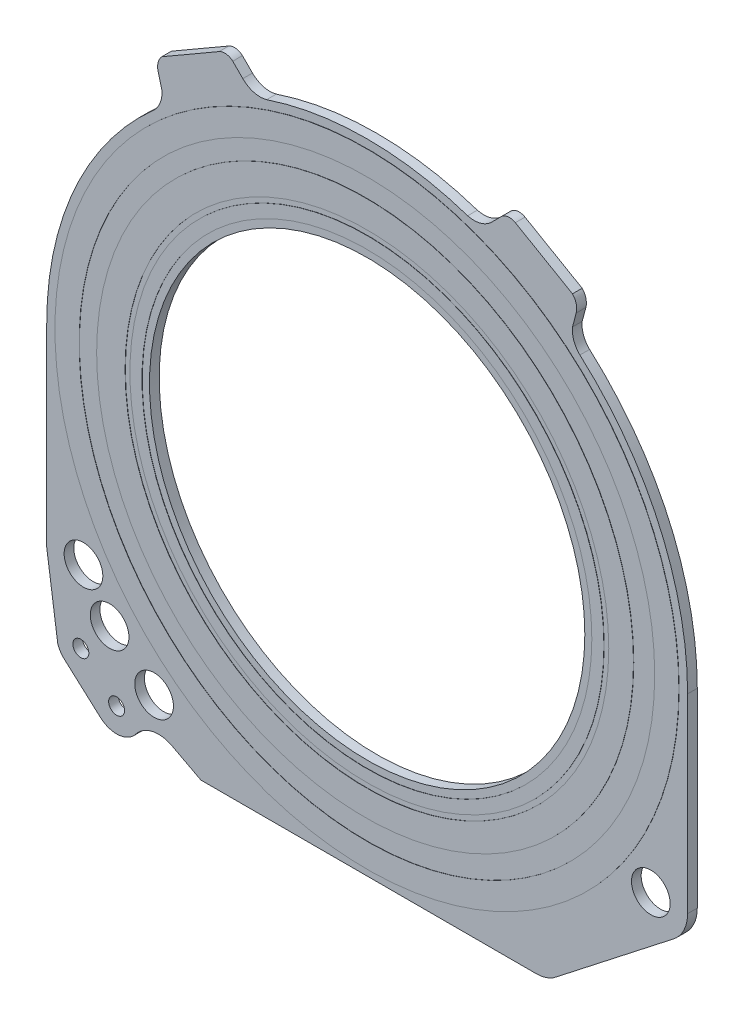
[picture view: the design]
ISO-10303-21;
HEADER;
FILE_DESCRIPTION(('STEP AP214'),'2;1');
FILE_NAME('part.step','',(''),(''),'','','');
FILE_SCHEMA(('AUTOMOTIVE_DESIGN { 1 0 10303 214 1 1 1 1 }'));
ENDSEC;
DATA;
#1=APPLICATION_CONTEXT('core data for automotive mechanical design processes');
#2=APPLICATION_PROTOCOL_DEFINITION('international standard','automotive_design',2000,#1);
#3=PRODUCT_CONTEXT('',#1,'mechanical');
#4=PRODUCT('Part','Part','',(#3));
#5=PRODUCT_RELATED_PRODUCT_CATEGORY('part','',(#4));
#6=PRODUCT_DEFINITION_FORMATION('','',#4);
#7=PRODUCT_DEFINITION_CONTEXT('part definition',#1,'design');
#8=PRODUCT_DEFINITION('design','',#6,#7);
#9=PRODUCT_DEFINITION_SHAPE('','',#8);
#10=(LENGTH_UNIT() NAMED_UNIT(*) SI_UNIT(.MILLI.,.METRE.));
#11=(NAMED_UNIT(*) PLANE_ANGLE_UNIT() SI_UNIT($,.RADIAN.));
#12=(NAMED_UNIT(*) SI_UNIT($,.STERADIAN.) SOLID_ANGLE_UNIT());
#13=UNCERTAINTY_MEASURE_WITH_UNIT(LENGTH_MEASURE(1.E-05),#10,'distance_accuracy_value','');
#14=(GEOMETRIC_REPRESENTATION_CONTEXT(3) GLOBAL_UNCERTAINTY_ASSIGNED_CONTEXT((#13)) GLOBAL_UNIT_ASSIGNED_CONTEXT((#10,
#11,#12)) REPRESENTATION_CONTEXT('',''));
#15=CARTESIAN_POINT('',(0.,0.,0.));
#16=DIRECTION('',(0.,0.,1.));
#17=DIRECTION('',(1.,0.,0.));
#18=AXIS2_PLACEMENT_3D('',#15,#16,#17);
#19=CARTESIAN_POINT('',(72.2071972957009,20.3682152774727,0.));
#20=DIRECTION('',(0.,0.,1.));
#21=DIRECTION('',(1.,0.,0.));
#22=AXIS2_PLACEMENT_3D('',#19,#20,#21);
#23=PLANE('',#22);
#24=CARTESIAN_POINT('',(72.2834094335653,20.3510273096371,0.));
#25=DIRECTION('',(0.,0.,1.));
#26=DIRECTION('',(1.,0.,0.));
#27=AXIS2_PLACEMENT_3D('',#24,#25,#26);
#28=CIRCLE('',#27,10.);
#29=CARTESIAN_POINT('',(82.2834094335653,20.3510273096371,0.));
#30=VERTEX_POINT('',#29);
#31=EDGE_CURVE('E25',#30,#30,#28,.F.);
#32=ORIENTED_EDGE('',*,*,#31,.F.);
#33=EDGE_LOOP('',(#32));
#34=FACE_BOUND('',#33,.T.);
#35=CARTESIAN_POINT('',(72.2834094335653,20.3510273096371,0.));
#36=DIRECTION('',(0.,0.,1.));
#37=DIRECTION('',(1.,0.,0.));
#38=AXIS2_PLACEMENT_3D('',#35,#36,#37);
#39=CIRCLE('',#38,9.79999999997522);
#40=CARTESIAN_POINT('',(82.0834094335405,20.3510273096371,0.));
#41=VERTEX_POINT('',#40);
#42=EDGE_CURVE('E462',#41,#41,#39,.T.);
#43=ORIENTED_EDGE('',*,*,#42,.F.);
#44=EDGE_LOOP('',(#43));
#45=FACE_BOUND('',#44,.T.);
#46=ADVANCED_FACE('F17',(#34,#45),#23,.T.);
#47=CARTESIAN_POINT('',(72.2834094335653,20.3510273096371,0.));
#48=DIRECTION('',(0.,0.,1.));
#49=DIRECTION('',(1.,0.,0.));
#50=AXIS2_PLACEMENT_3D('',#47,#48,#49);
#51=CIRCLE('',#50,11.9);
#52=CARTESIAN_POINT('',(84.1834094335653,20.3510273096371,0.));
#53=VERTEX_POINT('',#52);
#54=EDGE_CURVE('E396',#53,#53,#51,.F.);
#55=ORIENTED_EDGE('',*,*,#54,.F.);
#56=EDGE_LOOP('',(#55));
#57=FACE_BOUND('',#56,.T.);
#58=CARTESIAN_POINT('',(72.2071972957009,20.3682152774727,0.));
#59=DIRECTION('',(0.,0.,1.));
#60=DIRECTION('',(1.,0.,0.));
#61=AXIS2_PLACEMENT_3D('',#58,#59,#60);
#62=CIRCLE('',#61,11.1);
#63=CARTESIAN_POINT('',(83.3071972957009,20.3682152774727,0.));
#64=VERTEX_POINT('',#63);
#65=EDGE_CURVE('E472',#64,#64,#62,.T.);
#66=ORIENTED_EDGE('',*,*,#65,.F.);
#67=EDGE_LOOP('',(#66));
#68=FACE_BOUND('',#67,.T.);
#69=ADVANCED_FACE('F457',(#57,#68),#23,.T.);
#70=CARTESIAN_POINT('',(72.2071972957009,20.3682152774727,0.));
#71=DIRECTION('',(0.,0.,1.));
#72=DIRECTION('',(1.,0.,0.));
#73=AXIS2_PLACEMENT_3D('',#70,#71,#72);
#74=CIRCLE('',#73,13.173799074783);
#75=CARTESIAN_POINT('',(63.4602832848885,30.2191277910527,0.));
#76=VERTEX_POINT('',#75);
#77=CARTESIAN_POINT('',(59.0334094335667,20.3510273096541,0.));
#78=VERTEX_POINT('',#77);
#79=EDGE_CURVE('E210',#76,#78,#74,.T.);
#80=ORIENTED_EDGE('',*,*,#79,.T.);
#81=DIRECTION('',(0.,-1.,0.));
#82=VECTOR('',#81,1.);
#83=CARTESIAN_POINT('',(59.0334094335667,20.3510273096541,0.));
#84=LINE('',#83,#82);
#85=CARTESIAN_POINT('',(59.0334094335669,12.3510273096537,0.));
#86=VERTEX_POINT('',#85);
#87=EDGE_CURVE('E220',#78,#86,#84,.T.);
#88=ORIENTED_EDGE('',*,*,#87,.T.);
#89=DIRECTION('',(0.140192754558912,-0.990124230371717,0.));
#90=VECTOR('',#89,1.);
#91=CARTESIAN_POINT('',(59.0334094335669,12.3510273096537,0.));
#92=LINE('',#91,#90);
#93=CARTESIAN_POINT('',(59.4881770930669,9.1391888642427,0.));
#94=VERTEX_POINT('',#93);
#95=EDGE_CURVE('E225',#86,#94,#92,.T.);
#96=ORIENTED_EDGE('',*,*,#95,.T.);
#97=CARTESIAN_POINT('',(60.3937369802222,9.40788438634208,0.));
#98=DIRECTION('',(0.,0.,1.));
#99=DIRECTION('',(1.,0.,0.));
#100=AXIS2_PLACEMENT_3D('',#97,#98,#99);
#101=CIRCLE('',#100,0.944582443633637);
#102=CARTESIAN_POINT('',(59.79093414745,8.6806535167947,0.));
#103=VERTEX_POINT('',#102);
#104=EDGE_CURVE('E239',#94,#103,#101,.T.);
#105=ORIENTED_EDGE('',*,*,#104,.T.);
#106=DIRECTION('',(0.744428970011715,-0.667701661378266,0.));
#107=VECTOR('',#106,1.);
#108=CARTESIAN_POINT('',(59.79093414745,8.6806535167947,0.));
#109=LINE('',#108,#107);
#110=CARTESIAN_POINT('',(61.2703050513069,7.3537594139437,0.));
#111=VERTEX_POINT('',#110);
#112=EDGE_CURVE('E242',#103,#111,#109,.T.);
#113=ORIENTED_EDGE('',*,*,#112,.T.);
#114=CARTESIAN_POINT('',(61.9234094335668,8.11102730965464,0.));
#115=DIRECTION('',(0.,0.,1.));
#116=DIRECTION('',(1.,0.,0.));
#117=AXIS2_PLACEMENT_3D('',#114,#115,#116);
#118=CIRCLE('',#117,1.00000000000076);
#119=CARTESIAN_POINT('',(62.713227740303,7.4976864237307,0.));
#120=VERTEX_POINT('',#119);
#121=EDGE_CURVE('E245',#111,#120,#118,.T.);
#122=ORIENTED_EDGE('',*,*,#121,.T.);
#123=CARTESIAN_POINT('',(63.6597167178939,6.7821213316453,0.));
#124=DIRECTION('',(0.,0.,-1.));
#125=DIRECTION('',(1.,0.,0.));
#126=AXIS2_PLACEMENT_3D('',#123,#124,#125);
#127=CIRCLE('',#126,1.18653899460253);
#128=CARTESIAN_POINT('',(64.1660247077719,7.8552135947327,0.));
#129=VERTEX_POINT('',#128);
#130=EDGE_CURVE('E248',#120,#129,#127,.T.);
#131=ORIENTED_EDGE('',*,*,#130,.T.);
#132=DIRECTION('',(0.884984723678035,-0.465620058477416,0.));
#133=VECTOR('',#132,1.);
#134=CARTESIAN_POINT('',(64.1660247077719,7.8552135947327,0.));
#135=LINE('',#134,#133);
#136=CARTESIAN_POINT('',(65.4094094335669,7.2010273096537,0.));
#137=VERTEX_POINT('',#136);
#138=EDGE_CURVE('E251',#129,#137,#135,.T.);
#139=ORIENTED_EDGE('',*,*,#138,.T.);
#140=DIRECTION('',(1.,0.,0.));
#141=VECTOR('',#140,1.);
#142=CARTESIAN_POINT('',(65.4094094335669,7.2010273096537,0.));
#143=LINE('',#142,#141);
#144=CARTESIAN_POINT('',(79.2751515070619,7.2010273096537,0.));
#145=VERTEX_POINT('',#144);
#146=EDGE_CURVE('E254',#137,#145,#143,.T.);
#147=ORIENTED_EDGE('',*,*,#146,.T.);
#148=CARTESIAN_POINT('',(79.2751515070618,8.50102730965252,0.));
#149=DIRECTION('',(0.,0.,1.));
#150=DIRECTION('',(1.,0.,0.));
#151=AXIS2_PLACEMENT_3D('',#148,#149,#150);
#152=CIRCLE('',#151,1.29999999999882);
#153=CARTESIAN_POINT('',(80.1002135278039,7.4964016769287,0.));
#154=VERTEX_POINT('',#153);
#155=EDGE_CURVE('E257',#145,#154,#152,.T.);
#156=ORIENTED_EDGE('',*,*,#155,.T.);
#157=DIRECTION('',(0.78818503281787,0.615438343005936,0.));
#158=VECTOR('',#157,1.);
#159=CARTESIAN_POINT('',(80.1002135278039,7.4964016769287,0.));
#160=LINE('',#159,#158);
#161=CARTESIAN_POINT('',(84.9489566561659,11.2824446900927,0.));
#162=VERTEX_POINT('',#161);
#163=EDGE_CURVE('E260',#154,#162,#160,.T.);
#164=ORIENTED_EDGE('',*,*,#163,.T.);
#165=CARTESIAN_POINT('',(84.0134094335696,12.4804227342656,0.));
#166=DIRECTION('',(0.,0.,1.));
#167=DIRECTION('',(1.,0.,0.));
#168=AXIS2_PLACEMENT_3D('',#165,#166,#167);
#169=CIRCLE('',#168,1.52000000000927);
#170=CARTESIAN_POINT('',(85.5334094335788,12.4804227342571,0.));
#171=VERTEX_POINT('',#170);
#172=EDGE_CURVE('E263',#162,#171,#169,.T.);
#173=ORIENTED_EDGE('',*,*,#172,.T.);
#174=DIRECTION('',(0.,1.,0.));
#175=VECTOR('',#174,1.);
#176=CARTESIAN_POINT('',(85.5334094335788,12.4804227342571,0.));
#177=LINE('',#176,#175);
#178=CARTESIAN_POINT('',(85.5334094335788,20.3510273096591,0.));
#179=VERTEX_POINT('',#178);
#180=EDGE_CURVE('E266',#171,#179,#177,.T.);
#181=ORIENTED_EDGE('',*,*,#180,.T.);
#182=CARTESIAN_POINT('',(72.2834094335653,20.3510273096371,0.));
#183=DIRECTION('',(0.,0.,1.));
#184=DIRECTION('',(1.,0.,0.));
#185=AXIS2_PLACEMENT_3D('',#182,#183,#184);
#186=CIRCLE('',#185,13.2500000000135);
#187=CARTESIAN_POINT('',(81.0802834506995,30.2594836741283,0.));
#188=VERTEX_POINT('',#187);
#189=EDGE_CURVE('E269',#179,#188,#186,.T.);
#190=ORIENTED_EDGE('',*,*,#189,.T.);
#191=CARTESIAN_POINT('',(81.790227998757,30.9954268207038,0.));
#192=DIRECTION('',(0.,0.,-1.));
#193=DIRECTION('',(1.,0.,0.));
#194=AXIS2_PLACEMENT_3D('',#191,#192,#193);
#195=CIRCLE('',#194,1.02256226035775);
#196=CARTESIAN_POINT('',(80.7740510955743,31.1095236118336,0.));
#197=VERTEX_POINT('',#196);
#198=EDGE_CURVE('E272',#188,#197,#195,.T.);
#199=ORIENTED_EDGE('',*,*,#198,.T.);
#200=DIRECTION('',(0.255800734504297,0.966729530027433,0.));
#201=VECTOR('',#200,1.);
#202=CARTESIAN_POINT('',(80.7740510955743,31.1095236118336,0.));
#203=LINE('',#202,#201);
#204=CARTESIAN_POINT('',(80.9265181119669,31.6857313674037,0.));
#205=VERTEX_POINT('',#204);
#206=EDGE_CURVE('E275',#197,#205,#203,.T.);
#207=ORIENTED_EDGE('',*,*,#206,.T.);
#208=CARTESIAN_POINT('',(80.2953420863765,31.8527432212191,0.));
#209=DIRECTION('',(0.,0.,1.));
#210=DIRECTION('',(1.,0.,0.));
#211=AXIS2_PLACEMENT_3D('',#208,#209,#210);
#212=CIRCLE('',#211,0.652898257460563);
#213=CARTESIAN_POINT('',(80.7740510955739,32.2967182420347,0.));
#214=VERTEX_POINT('',#213);
#215=EDGE_CURVE('E278',#205,#214,#212,.T.);
#216=ORIENTED_EDGE('',*,*,#215,.T.);
#217=DIRECTION('',(-0.865868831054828,0.500271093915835,0.));
#218=VECTOR('',#217,1.);
#219=CARTESIAN_POINT('',(80.7740510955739,32.2967182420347,0.));
#220=LINE('',#219,#218);
#221=CARTESIAN_POINT('',(78.411036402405,33.6619919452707,0.));
#222=VERTEX_POINT('',#221);
#223=EDGE_CURVE('E281',#214,#222,#220,.T.);
#224=ORIENTED_EDGE('',*,*,#223,.T.);
#225=CARTESIAN_POINT('',(78.1669553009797,33.2395365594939,0.));
#226=DIRECTION('',(0.,0.,1.));
#227=DIRECTION('',(1.,0.,0.));
#228=AXIS2_PLACEMENT_3D('',#225,#226,#227);
#229=CIRCLE('',#228,0.487897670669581);
#230=CARTESIAN_POINT('',(77.8410630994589,33.6026321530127,0.));
#231=VERTEX_POINT('',#230);
#232=EDGE_CURVE('E284',#222,#231,#229,.T.);
#233=ORIENTED_EDGE('',*,*,#232,.T.);
#234=DIRECTION('',(-0.707181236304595,-0.70703231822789,0.));
#235=VECTOR('',#234,1.);
#236=CARTESIAN_POINT('',(77.4254574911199,33.1871140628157,0.));
#237=LINE('',#236,#235);
#238=CARTESIAN_POINT('',(77.4254574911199,33.1871140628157,0.));
#239=VERTEX_POINT('',#238);
#240=EDGE_CURVE('E287',#231,#239,#237,.T.);
#241=ORIENTED_EDGE('',*,*,#240,.T.);
#242=CARTESIAN_POINT('',(76.7078520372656,33.9048706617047,0.));
#243=DIRECTION('',(0.,0.,-1.));
#244=DIRECTION('',(1.,0.,0.));
#245=AXIS2_PLACEMENT_3D('',#242,#243,#244);
#246=CIRCLE('',#245,1.01495424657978);
#247=CARTESIAN_POINT('',(76.4398783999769,32.9259313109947,0.));
#248=VERTEX_POINT('',#247);
#249=EDGE_CURVE('E290',#239,#248,#246,.T.);
#250=ORIENTED_EDGE('',*,*,#249,.T.);
#251=CARTESIAN_POINT('',(72.283409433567,20.4673099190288,0.));
#252=DIRECTION('',(0.,0.,1.));
#253=DIRECTION('',(1.,0.,0.));
#254=AXIS2_PLACEMENT_3D('',#251,#252,#253);
#255=CIRCLE('',#254,13.1336773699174);
#256=CARTESIAN_POINT('',(68.1269404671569,32.9259313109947,0.));
#257=VERTEX_POINT('',#256);
#258=EDGE_CURVE('E293',#248,#257,#255,.T.);
#259=ORIENTED_EDGE('',*,*,#258,.T.);
#260=CARTESIAN_POINT('',(67.8589668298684,33.9048706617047,0.));
#261=DIRECTION('',(0.,0.,-1.));
#262=DIRECTION('',(1.,0.,0.));
#263=AXIS2_PLACEMENT_3D('',#260,#261,#262);
#264=CIRCLE('',#263,1.01495424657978);
#265=CARTESIAN_POINT('',(67.1413613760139,33.1871140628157,0.));
#266=VERTEX_POINT('',#265);
#267=EDGE_CURVE('E296',#257,#266,#264,.T.);
#268=ORIENTED_EDGE('',*,*,#267,.T.);
#269=DIRECTION('',(-0.707181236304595,0.70703231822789,0.));
#270=VECTOR('',#269,1.);
#271=CARTESIAN_POINT('',(67.1413613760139,33.1871140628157,0.));
#272=LINE('',#271,#270);
#273=CARTESIAN_POINT('',(66.7257557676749,33.6026321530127,0.));
#274=VERTEX_POINT('',#273);
#275=EDGE_CURVE('E299',#266,#274,#272,.T.);
#276=ORIENTED_EDGE('',*,*,#275,.T.);
#277=CARTESIAN_POINT('',(66.3998635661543,33.2395365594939,0.));
#278=DIRECTION('',(0.,0.,1.));
#279=DIRECTION('',(1.,0.,0.));
#280=AXIS2_PLACEMENT_3D('',#277,#278,#279);
#281=CIRCLE('',#280,0.487897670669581);
#282=CARTESIAN_POINT('',(66.155782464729,33.6619919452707,0.));
#283=VERTEX_POINT('',#282);
#284=EDGE_CURVE('E302',#274,#283,#281,.T.);
#285=ORIENTED_EDGE('',*,*,#284,.T.);
#286=DIRECTION('',(-0.865868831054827,-0.500271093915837,0.));
#287=VECTOR('',#286,1.);
#288=CARTESIAN_POINT('',(63.7927677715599,32.2967182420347,0.));
#289=LINE('',#288,#287);
#290=CARTESIAN_POINT('',(63.7927677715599,32.2967182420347,0.));
#291=VERTEX_POINT('',#290);
#292=EDGE_CURVE('E305',#283,#291,#289,.T.);
#293=ORIENTED_EDGE('',*,*,#292,.T.);
#294=CARTESIAN_POINT('',(64.2714767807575,31.8527432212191,0.));
#295=DIRECTION('',(0.,0.,1.));
#296=DIRECTION('',(1.,0.,0.));
#297=AXIS2_PLACEMENT_3D('',#294,#295,#296);
#298=CIRCLE('',#297,0.652898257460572);
#299=CARTESIAN_POINT('',(63.6403007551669,31.6857313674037,0.));
#300=VERTEX_POINT('',#299);
#301=EDGE_CURVE('E308',#291,#300,#298,.T.);
#302=ORIENTED_EDGE('',*,*,#301,.T.);
#303=DIRECTION('',(0.255800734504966,-0.966729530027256,0.));
#304=VECTOR('',#303,1.);
#305=CARTESIAN_POINT('',(63.6403007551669,31.6857313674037,0.));
#306=LINE('',#305,#304);
#307=CARTESIAN_POINT('',(63.7927677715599,31.1095236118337,0.));
#308=VERTEX_POINT('',#307);
#309=EDGE_CURVE('E311',#300,#308,#306,.T.);
#310=ORIENTED_EDGE('',*,*,#309,.T.);
#311=CARTESIAN_POINT('',(62.7210654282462,31.0024353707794,0.));
#312=DIRECTION('',(0.,0.,-1.));
#313=DIRECTION('',(1.,0.,0.));
#314=AXIS2_PLACEMENT_3D('',#311,#312,#313);
#315=CIRCLE('',#314,1.07703936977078);
#316=EDGE_CURVE('E230',#308,#76,#315,.T.);
#317=ORIENTED_EDGE('',*,*,#316,.T.);
#318=EDGE_LOOP('',(#80,#88,#96,#105,#113,#122,#131,#139,#147,#156,#164,#173,#181,#190,#199,#207,
#216,#224,#233,#241,#250,#259,#268,#276,#285,#293,#302,#310,#317));
#319=FACE_BOUND('',#318,.T.);
#320=CARTESIAN_POINT('',(84.0134094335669,12.4810273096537,0.));
#321=DIRECTION('',(0.,0.,1.));
#322=DIRECTION('',(1.,0.,0.));
#323=AXIS2_PLACEMENT_3D('',#320,#321,#322);
#324=CIRCLE('',#323,0.8);
#325=CARTESIAN_POINT('',(84.8134094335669,12.4810273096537,0.));
#326=VERTEX_POINT('',#325);
#327=EDGE_CURVE('E234',#326,#326,#324,.T.);
#328=ORIENTED_EDGE('',*,*,#327,.F.);
#329=EDGE_LOOP('',(#328));
#330=FACE_BOUND('',#329,.T.);
#331=CARTESIAN_POINT('',(63.4734094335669,9.2810273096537,0.));
#332=DIRECTION('',(0.,0.,1.));
#333=DIRECTION('',(1.,0.,0.));
#334=AXIS2_PLACEMENT_3D('',#331,#332,#333);
#335=CIRCLE('',#334,0.8);
#336=CARTESIAN_POINT('',(64.2734094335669,9.2810273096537,0.));
#337=VERTEX_POINT('',#336);
#338=EDGE_CURVE('E520',#337,#337,#335,.T.);
#339=ORIENTED_EDGE('',*,*,#338,.F.);
#340=EDGE_LOOP('',(#339));
#341=FACE_BOUND('',#340,.T.);
#342=CARTESIAN_POINT('',(61.6334094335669,10.8310273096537,0.));
#343=DIRECTION('',(0.,0.,1.));
#344=DIRECTION('',(1.,0.,0.));
#345=AXIS2_PLACEMENT_3D('',#342,#343,#344);
#346=CIRCLE('',#345,0.8);
#347=CARTESIAN_POINT('',(62.4334094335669,10.8310273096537,0.));
#348=VERTEX_POINT('',#347);
#349=EDGE_CURVE('E514',#348,#348,#346,.T.);
#350=ORIENTED_EDGE('',*,*,#349,.F.);
#351=EDGE_LOOP('',(#350));
#352=FACE_BOUND('',#351,.T.);
#353=CARTESIAN_POINT('',(60.553409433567,12.4810273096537,0.));
#354=DIRECTION('',(0.,0.,1.));
#355=DIRECTION('',(1.,0.,0.));
#356=AXIS2_PLACEMENT_3D('',#353,#354,#355);
#357=CIRCLE('',#356,0.8);
#358=CARTESIAN_POINT('',(61.353409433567,12.4810273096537,0.));
#359=VERTEX_POINT('',#358);
#360=EDGE_CURVE('E508',#359,#359,#357,.T.);
#361=ORIENTED_EDGE('',*,*,#360,.F.);
#362=EDGE_LOOP('',(#361));
#363=FACE_BOUND('',#362,.T.);
#364=CARTESIAN_POINT('',(60.4444881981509,9.4315398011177,0.));
#365=DIRECTION('',(0.,0.,1.));
#366=DIRECTION('',(1.,0.,0.));
#367=AXIS2_PLACEMENT_3D('',#364,#365,#366);
#368=CIRCLE('',#367,0.33);
#369=CARTESIAN_POINT('',(60.7744881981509,9.4315398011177,0.));
#370=VERTEX_POINT('',#369);
#371=EDGE_CURVE('E502',#370,#370,#368,.T.);
#372=ORIENTED_EDGE('',*,*,#371,.F.);
#373=EDGE_LOOP('',(#372));
#374=FACE_BOUND('',#373,.T.);
#375=CARTESIAN_POINT('',(61.9234094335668,8.11102730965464,0.));
#376=DIRECTION('',(0.,0.,1.));
#377=DIRECTION('',(1.,0.,0.));
#378=AXIS2_PLACEMENT_3D('',#375,#376,#377);
#379=CIRCLE('',#378,0.330000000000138);
#380=CARTESIAN_POINT('',(62.2534094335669,8.11102730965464,0.));
#381=VERTEX_POINT('',#380);
#382=EDGE_CURVE('E496',#381,#381,#379,.T.);
#383=ORIENTED_EDGE('',*,*,#382,.F.);
#384=EDGE_LOOP('',(#383));
#385=FACE_BOUND('',#384,.T.);
#386=CARTESIAN_POINT('',(72.2834094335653,20.3510273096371,0.));
#387=DIRECTION('',(0.,0.,1.));
#388=DIRECTION('',(1.,0.,0.));
#389=AXIS2_PLACEMENT_3D('',#386,#387,#388);
#390=CIRCLE('',#389,12.9);
#391=CARTESIAN_POINT('',(85.1834094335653,20.3510273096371,0.));
#392=VERTEX_POINT('',#391);
#393=EDGE_CURVE('E481',#392,#392,#390,.T.);
#394=ORIENTED_EDGE('',*,*,#393,.F.);
#395=EDGE_LOOP('',(#394));
#396=FACE_BOUND('',#395,.T.);
#397=ADVANCED_FACE('F227',(#319,#330,#341,#352,#363,#374,#385,#396),#23,.T.);
#398=CARTESIAN_POINT('',(72.2071972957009,20.3682152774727,-0.4));
#399=DIRECTION('',(0.,0.,1.));
#400=DIRECTION('',(1.,0.,0.));
#401=AXIS2_PLACEMENT_3D('',#398,#399,#400);
#402=CYLINDRICAL_SURFACE('',#401,13.173799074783);
#403=ORIENTED_EDGE('',*,*,#79,.F.);
#404=DIRECTION('',(0.,0.,1.));
#405=VECTOR('',#404,1.);
#406=CARTESIAN_POINT('',(63.4602832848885,30.2191277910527,-0.4));
#407=LINE('',#406,#405);
#408=CARTESIAN_POINT('',(63.4602832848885,30.2191277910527,-0.4));
#409=VERTEX_POINT('',#408);
#410=EDGE_CURVE('E32',#409,#76,#407,.T.);
#411=ORIENTED_EDGE('',*,*,#410,.F.);
#412=CARTESIAN_POINT('',(72.2071972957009,20.3682152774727,-0.4));
#413=DIRECTION('',(0.,0.,1.));
#414=DIRECTION('',(1.,0.,0.));
#415=AXIS2_PLACEMENT_3D('',#412,#413,#414);
#416=CIRCLE('',#415,13.173799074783);
#417=CARTESIAN_POINT('',(59.0334094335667,20.3510273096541,-0.4));
#418=VERTEX_POINT('',#417);
#419=EDGE_CURVE('E212',#409,#418,#416,.T.);
#420=ORIENTED_EDGE('',*,*,#419,.T.);
#421=DIRECTION('',(0.,0.,1.));
#422=VECTOR('',#421,1.);
#423=CARTESIAN_POINT('',(59.0334094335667,20.3510273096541,-0.4));
#424=LINE('',#423,#422);
#425=EDGE_CURVE('E207',#418,#78,#424,.T.);
#426=ORIENTED_EDGE('',*,*,#425,.T.);
#427=EDGE_LOOP('',(#403,#411,#420,#426));
#428=FACE_BOUND('',#427,.T.);
#429=ADVANCED_FACE('F19',(#428),#402,.T.);
#430=CARTESIAN_POINT('',(62.7210654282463,31.0024353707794,-0.4));
#431=DIRECTION('',(0.,0.,1.));
#432=DIRECTION('',(1.,0.,0.));
#433=AXIS2_PLACEMENT_3D('',#430,#431,#432);
#434=CYLINDRICAL_SURFACE('',#433,1.07703936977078);
#435=ORIENTED_EDGE('',*,*,#316,.F.);
#436=DIRECTION('',(0.,0.,1.));
#437=VECTOR('',#436,1.);
#438=CARTESIAN_POINT('',(63.79276777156,31.1095236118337,-0.4));
#439=LINE('',#438,#437);
#440=CARTESIAN_POINT('',(63.79276777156,31.1095236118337,-0.4));
#441=VERTEX_POINT('',#440);
#442=EDGE_CURVE('E40',#441,#308,#439,.T.);
#443=ORIENTED_EDGE('',*,*,#442,.F.);
#444=CARTESIAN_POINT('',(62.7210654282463,31.0024353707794,-0.4));
#445=DIRECTION('',(0.,0.,-1.));
#446=DIRECTION('',(1.,0.,0.));
#447=AXIS2_PLACEMENT_3D('',#444,#445,#446);
#448=CIRCLE('',#447,1.07703936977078);
#449=EDGE_CURVE('E217',#441,#409,#448,.T.);
#450=ORIENTED_EDGE('',*,*,#449,.T.);
#451=ORIENTED_EDGE('',*,*,#410,.T.);
#452=EDGE_LOOP('',(#435,#443,#450,#451));
#453=FACE_BOUND('',#452,.T.);
#454=ADVANCED_FACE('F594',(#453),#434,.F.);
#455=CARTESIAN_POINT('',(63.6403007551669,31.6857313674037,-0.4));
#456=DIRECTION('',(-0.966729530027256,-0.255800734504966,0.));
#457=DIRECTION('',(0.255800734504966,-0.966729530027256,0.));
#458=AXIS2_PLACEMENT_3D('',#455,#456,#457);
#459=PLANE('',#458);
#460=ORIENTED_EDGE('',*,*,#309,.F.);
#461=DIRECTION('',(0.,0.,1.));
#462=VECTOR('',#461,1.);
#463=CARTESIAN_POINT('',(63.6403007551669,31.6857313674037,-0.4));
#464=LINE('',#463,#462);
#465=CARTESIAN_POINT('',(63.6403007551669,31.6857313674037,-0.4));
#466=VERTEX_POINT('',#465);
#467=EDGE_CURVE('E398',#466,#300,#464,.T.);
#468=ORIENTED_EDGE('',*,*,#467,.F.);
#469=DIRECTION('',(0.255800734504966,-0.966729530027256,0.));
#470=VECTOR('',#469,1.);
#471=CARTESIAN_POINT('',(63.6403007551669,31.6857313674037,-0.4));
#472=LINE('',#471,#470);
#473=EDGE_CURVE('E392',#466,#441,#472,.T.);
#474=ORIENTED_EDGE('',*,*,#473,.T.);
#475=ORIENTED_EDGE('',*,*,#442,.T.);
#476=EDGE_LOOP('',(#460,#468,#474,#475));
#477=FACE_BOUND('',#476,.T.);
#478=ADVANCED_FACE('F597',(#477),#459,.T.);
#479=CARTESIAN_POINT('',(64.2714767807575,31.8527432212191,-0.4));
#480=DIRECTION('',(0.,0.,1.));
#481=DIRECTION('',(1.,0.,0.));
#482=AXIS2_PLACEMENT_3D('',#479,#480,#481);
#483=CYLINDRICAL_SURFACE('',#482,0.652898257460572);
#484=ORIENTED_EDGE('',*,*,#301,.F.);
#485=DIRECTION('',(0.,0.,1.));
#486=VECTOR('',#485,1.);
#487=CARTESIAN_POINT('',(63.7927677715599,32.2967182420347,-0.4));
#488=LINE('',#487,#486);
#489=CARTESIAN_POINT('',(63.7927677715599,32.2967182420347,-0.4));
#490=VERTEX_POINT('',#489);
#491=EDGE_CURVE('E400',#490,#291,#488,.T.);
#492=ORIENTED_EDGE('',*,*,#491,.F.);
#493=CARTESIAN_POINT('',(64.2714767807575,31.8527432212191,-0.4));
#494=DIRECTION('',(0.,0.,1.));
#495=DIRECTION('',(1.,0.,0.));
#496=AXIS2_PLACEMENT_3D('',#493,#494,#495);
#497=CIRCLE('',#496,0.652898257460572);
#498=EDGE_CURVE('E389',#490,#466,#497,.T.);
#499=ORIENTED_EDGE('',*,*,#498,.T.);
#500=ORIENTED_EDGE('',*,*,#467,.T.);
#501=EDGE_LOOP('',(#484,#492,#499,#500));
#502=FACE_BOUND('',#501,.T.);
#503=ADVANCED_FACE('F600',(#502),#483,.T.);
#504=CARTESIAN_POINT('',(63.7927677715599,32.2967182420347,-0.4));
#505=DIRECTION('',(-0.500271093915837,0.865868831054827,0.));
#506=DIRECTION('',(-0.865868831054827,-0.500271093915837,0.));
#507=AXIS2_PLACEMENT_3D('',#504,#505,#506);
#508=PLANE('',#507);
#509=ORIENTED_EDGE('',*,*,#292,.F.);
#510=DIRECTION('',(0.,0.,1.));
#511=VECTOR('',#510,1.);
#512=CARTESIAN_POINT('',(66.155782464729,33.6619919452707,-0.4));
#513=LINE('',#512,#511);
#514=CARTESIAN_POINT('',(66.155782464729,33.6619919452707,-0.4));
#515=VERTEX_POINT('',#514);
#516=EDGE_CURVE('E402',#515,#283,#513,.T.);
#517=ORIENTED_EDGE('',*,*,#516,.F.);
#518=DIRECTION('',(-0.865868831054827,-0.500271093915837,0.));
#519=VECTOR('',#518,1.);
#520=CARTESIAN_POINT('',(63.7927677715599,32.2967182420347,-0.4));
#521=LINE('',#520,#519);
#522=EDGE_CURVE('E386',#515,#490,#521,.T.);
#523=ORIENTED_EDGE('',*,*,#522,.T.);
#524=ORIENTED_EDGE('',*,*,#491,.T.);
#525=EDGE_LOOP('',(#509,#517,#523,#524));
#526=FACE_BOUND('',#525,.T.);
#527=ADVANCED_FACE('F604',(#526),#508,.T.);
#528=CARTESIAN_POINT('',(66.3998635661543,33.2395365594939,-0.4));
#529=DIRECTION('',(0.,0.,1.));
#530=DIRECTION('',(1.,0.,0.));
#531=AXIS2_PLACEMENT_3D('',#528,#529,#530);
#532=CYLINDRICAL_SURFACE('',#531,0.487897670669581);
#533=ORIENTED_EDGE('',*,*,#284,.F.);
#534=DIRECTION('',(0.,0.,1.));
#535=VECTOR('',#534,1.);
#536=CARTESIAN_POINT('',(66.7257557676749,33.6026321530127,-0.4));
#537=LINE('',#536,#535);
#538=CARTESIAN_POINT('',(66.7257557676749,33.6026321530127,-0.4));
#539=VERTEX_POINT('',#538);
#540=EDGE_CURVE('E404',#539,#274,#537,.T.);
#541=ORIENTED_EDGE('',*,*,#540,.F.);
#542=CARTESIAN_POINT('',(66.3998635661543,33.2395365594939,-0.4));
#543=DIRECTION('',(0.,0.,1.));
#544=DIRECTION('',(1.,0.,0.));
#545=AXIS2_PLACEMENT_3D('',#542,#543,#544);
#546=CIRCLE('',#545,0.487897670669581);
#547=EDGE_CURVE('E383',#539,#515,#546,.T.);
#548=ORIENTED_EDGE('',*,*,#547,.T.);
#549=ORIENTED_EDGE('',*,*,#516,.T.);
#550=EDGE_LOOP('',(#533,#541,#548,#549));
#551=FACE_BOUND('',#550,.T.);
#552=ADVANCED_FACE('F608',(#551),#532,.T.);
#553=CARTESIAN_POINT('',(67.141361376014,33.1871140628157,-0.4));
#554=DIRECTION('',(0.70703231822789,0.707181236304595,0.));
#555=DIRECTION('',(-0.707181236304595,0.70703231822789,0.));
#556=AXIS2_PLACEMENT_3D('',#553,#554,#555);
#557=PLANE('',#556);
#558=ORIENTED_EDGE('',*,*,#275,.F.);
#559=DIRECTION('',(0.,0.,1.));
#560=VECTOR('',#559,1.);
#561=CARTESIAN_POINT('',(67.141361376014,33.1871140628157,-0.4));
#562=LINE('',#561,#560);
#563=CARTESIAN_POINT('',(67.141361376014,33.1871140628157,-0.4));
#564=VERTEX_POINT('',#563);
#565=EDGE_CURVE('E406',#564,#266,#562,.T.);
#566=ORIENTED_EDGE('',*,*,#565,.F.);
#567=DIRECTION('',(-0.707181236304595,0.70703231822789,0.));
#568=VECTOR('',#567,1.);
#569=CARTESIAN_POINT('',(67.141361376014,33.1871140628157,-0.4));
#570=LINE('',#569,#568);
#571=EDGE_CURVE('E380',#564,#539,#570,.T.);
#572=ORIENTED_EDGE('',*,*,#571,.T.);
#573=ORIENTED_EDGE('',*,*,#540,.T.);
#574=EDGE_LOOP('',(#558,#566,#572,#573));
#575=FACE_BOUND('',#574,.T.);
#576=ADVANCED_FACE('F612',(#575),#557,.T.);
#577=CARTESIAN_POINT('',(67.8589668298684,33.9048706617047,-0.4));
#578=DIRECTION('',(0.,0.,1.));
#579=DIRECTION('',(1.,0.,0.));
#580=AXIS2_PLACEMENT_3D('',#577,#578,#579);
#581=CYLINDRICAL_SURFACE('',#580,1.01495424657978);
#582=ORIENTED_EDGE('',*,*,#267,.F.);
#583=DIRECTION('',(0.,0.,1.));
#584=VECTOR('',#583,1.);
#585=CARTESIAN_POINT('',(68.1269404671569,32.9259313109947,-0.4));
#586=LINE('',#585,#584);
#587=CARTESIAN_POINT('',(68.1269404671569,32.9259313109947,-0.4));
#588=VERTEX_POINT('',#587);
#589=EDGE_CURVE('E408',#588,#257,#586,.T.);
#590=ORIENTED_EDGE('',*,*,#589,.F.);
#591=CARTESIAN_POINT('',(67.8589668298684,33.9048706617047,-0.4));
#592=DIRECTION('',(0.,0.,-1.));
#593=DIRECTION('',(1.,0.,0.));
#594=AXIS2_PLACEMENT_3D('',#591,#592,#593);
#595=CIRCLE('',#594,1.01495424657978);
#596=EDGE_CURVE('E377',#588,#564,#595,.T.);
#597=ORIENTED_EDGE('',*,*,#596,.T.);
#598=ORIENTED_EDGE('',*,*,#565,.T.);
#599=EDGE_LOOP('',(#582,#590,#597,#598));
#600=FACE_BOUND('',#599,.T.);
#601=ADVANCED_FACE('F616',(#600),#581,.F.);
#602=CARTESIAN_POINT('',(72.283409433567,20.4673099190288,-0.4));
#603=DIRECTION('',(0.,0.,1.));
#604=DIRECTION('',(1.,0.,0.));
#605=AXIS2_PLACEMENT_3D('',#602,#603,#604);
#606=CYLINDRICAL_SURFACE('',#605,13.1336773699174);
#607=ORIENTED_EDGE('',*,*,#258,.F.);
#608=DIRECTION('',(0.,0.,1.));
#609=VECTOR('',#608,1.);
#610=CARTESIAN_POINT('',(76.4398783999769,32.9259313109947,-0.4));
#611=LINE('',#610,#609);
#612=CARTESIAN_POINT('',(76.4398783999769,32.9259313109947,-0.4));
#613=VERTEX_POINT('',#612);
#614=EDGE_CURVE('E410',#613,#248,#611,.T.);
#615=ORIENTED_EDGE('',*,*,#614,.F.);
#616=CARTESIAN_POINT('',(72.283409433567,20.4673099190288,-0.4));
#617=DIRECTION('',(0.,0.,1.));
#618=DIRECTION('',(1.,0.,0.));
#619=AXIS2_PLACEMENT_3D('',#616,#617,#618);
#620=CIRCLE('',#619,13.1336773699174);
#621=EDGE_CURVE('E374',#613,#588,#620,.T.);
#622=ORIENTED_EDGE('',*,*,#621,.T.);
#623=ORIENTED_EDGE('',*,*,#589,.T.);
#624=EDGE_LOOP('',(#607,#615,#622,#623));
#625=FACE_BOUND('',#624,.T.);
#626=ADVANCED_FACE('F620',(#625),#606,.T.);
#627=CARTESIAN_POINT('',(76.7078520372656,33.9048706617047,-0.4));
#628=DIRECTION('',(0.,0.,1.));
#629=DIRECTION('',(1.,0.,0.));
#630=AXIS2_PLACEMENT_3D('',#627,#628,#629);
#631=CYLINDRICAL_SURFACE('',#630,1.01495424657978);
#632=ORIENTED_EDGE('',*,*,#249,.F.);
#633=DIRECTION('',(0.,0.,1.));
#634=VECTOR('',#633,1.);
#635=CARTESIAN_POINT('',(77.42545749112,33.1871140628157,-0.4));
#636=LINE('',#635,#634);
#637=CARTESIAN_POINT('',(77.42545749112,33.1871140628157,-0.4));
#638=VERTEX_POINT('',#637);
#639=EDGE_CURVE('E412',#638,#239,#636,.T.);
#640=ORIENTED_EDGE('',*,*,#639,.F.);
#641=CARTESIAN_POINT('',(76.7078520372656,33.9048706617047,-0.4));
#642=DIRECTION('',(0.,0.,-1.));
#643=DIRECTION('',(1.,0.,0.));
#644=AXIS2_PLACEMENT_3D('',#641,#642,#643);
#645=CIRCLE('',#644,1.01495424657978);
#646=EDGE_CURVE('E371',#638,#613,#645,.T.);
#647=ORIENTED_EDGE('',*,*,#646,.T.);
#648=ORIENTED_EDGE('',*,*,#614,.T.);
#649=EDGE_LOOP('',(#632,#640,#647,#648));
#650=FACE_BOUND('',#649,.T.);
#651=ADVANCED_FACE('F624',(#650),#631,.F.);
#652=CARTESIAN_POINT('',(77.42545749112,33.1871140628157,-0.4));
#653=DIRECTION('',(-0.70703231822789,0.707181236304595,0.));
#654=DIRECTION('',(-0.707181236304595,-0.70703231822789,0.));
#655=AXIS2_PLACEMENT_3D('',#652,#653,#654);
#656=PLANE('',#655);
#657=ORIENTED_EDGE('',*,*,#240,.F.);
#658=DIRECTION('',(0.,0.,1.));
#659=VECTOR('',#658,1.);
#660=CARTESIAN_POINT('',(77.8410630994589,33.6026321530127,-0.4));
#661=LINE('',#660,#659);
#662=CARTESIAN_POINT('',(77.8410630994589,33.6026321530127,-0.4));
#663=VERTEX_POINT('',#662);
#664=EDGE_CURVE('E414',#663,#231,#661,.T.);
#665=ORIENTED_EDGE('',*,*,#664,.F.);
#666=DIRECTION('',(-0.707181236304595,-0.70703231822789,0.));
#667=VECTOR('',#666,1.);
#668=CARTESIAN_POINT('',(77.42545749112,33.1871140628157,-0.4));
#669=LINE('',#668,#667);
#670=EDGE_CURVE('E368',#663,#638,#669,.T.);
#671=ORIENTED_EDGE('',*,*,#670,.T.);
#672=ORIENTED_EDGE('',*,*,#639,.T.);
#673=EDGE_LOOP('',(#657,#665,#671,#672));
#674=FACE_BOUND('',#673,.T.);
#675=ADVANCED_FACE('F628',(#674),#656,.T.);
#676=CARTESIAN_POINT('',(78.1669553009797,33.2395365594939,-0.4));
#677=DIRECTION('',(0.,0.,1.));
#678=DIRECTION('',(1.,0.,0.));
#679=AXIS2_PLACEMENT_3D('',#676,#677,#678);
#680=CYLINDRICAL_SURFACE('',#679,0.487897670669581);
#681=ORIENTED_EDGE('',*,*,#232,.F.);
#682=DIRECTION('',(0.,0.,1.));
#683=VECTOR('',#682,1.);
#684=CARTESIAN_POINT('',(78.411036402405,33.6619919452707,-0.4));
#685=LINE('',#684,#683);
#686=CARTESIAN_POINT('',(78.411036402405,33.6619919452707,-0.4));
#687=VERTEX_POINT('',#686);
#688=EDGE_CURVE('E416',#687,#222,#685,.T.);
#689=ORIENTED_EDGE('',*,*,#688,.F.);
#690=CARTESIAN_POINT('',(78.1669553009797,33.2395365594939,-0.4));
#691=DIRECTION('',(0.,0.,1.));
#692=DIRECTION('',(1.,0.,0.));
#693=AXIS2_PLACEMENT_3D('',#690,#691,#692);
#694=CIRCLE('',#693,0.487897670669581);
#695=EDGE_CURVE('E365',#687,#663,#694,.T.);
#696=ORIENTED_EDGE('',*,*,#695,.T.);
#697=ORIENTED_EDGE('',*,*,#664,.T.);
#698=EDGE_LOOP('',(#681,#689,#696,#697));
#699=FACE_BOUND('',#698,.T.);
#700=ADVANCED_FACE('F632',(#699),#680,.T.);
#701=CARTESIAN_POINT('',(80.7740510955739,32.2967182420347,-0.4));
#702=DIRECTION('',(0.500271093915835,0.865868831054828,0.));
#703=DIRECTION('',(-0.865868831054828,0.500271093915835,0.));
#704=AXIS2_PLACEMENT_3D('',#701,#702,#703);
#705=PLANE('',#704);
#706=ORIENTED_EDGE('',*,*,#223,.F.);
#707=DIRECTION('',(0.,0.,1.));
#708=VECTOR('',#707,1.);
#709=CARTESIAN_POINT('',(80.7740510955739,32.2967182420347,-0.4));
#710=LINE('',#709,#708);
#711=CARTESIAN_POINT('',(80.7740510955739,32.2967182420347,-0.4));
#712=VERTEX_POINT('',#711);
#713=EDGE_CURVE('E418',#712,#214,#710,.T.);
#714=ORIENTED_EDGE('',*,*,#713,.F.);
#715=DIRECTION('',(-0.865868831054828,0.500271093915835,0.));
#716=VECTOR('',#715,1.);
#717=CARTESIAN_POINT('',(80.7740510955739,32.2967182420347,-0.4));
#718=LINE('',#717,#716);
#719=EDGE_CURVE('E362',#712,#687,#718,.T.);
#720=ORIENTED_EDGE('',*,*,#719,.T.);
#721=ORIENTED_EDGE('',*,*,#688,.T.);
#722=EDGE_LOOP('',(#706,#714,#720,#721));
#723=FACE_BOUND('',#722,.T.);
#724=ADVANCED_FACE('F636',(#723),#705,.T.);
#725=CARTESIAN_POINT('',(80.2953420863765,31.8527432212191,-0.4));
#726=DIRECTION('',(0.,0.,1.));
#727=DIRECTION('',(1.,0.,0.));
#728=AXIS2_PLACEMENT_3D('',#725,#726,#727);
#729=CYLINDRICAL_SURFACE('',#728,0.652898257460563);
#730=ORIENTED_EDGE('',*,*,#215,.F.);
#731=DIRECTION('',(0.,0.,1.));
#732=VECTOR('',#731,1.);
#733=CARTESIAN_POINT('',(80.9265181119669,31.6857313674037,-0.4));
#734=LINE('',#733,#732);
#735=CARTESIAN_POINT('',(80.9265181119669,31.6857313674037,-0.4));
#736=VERTEX_POINT('',#735);
#737=EDGE_CURVE('E420',#736,#205,#734,.T.);
#738=ORIENTED_EDGE('',*,*,#737,.F.);
#739=CARTESIAN_POINT('',(80.2953420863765,31.8527432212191,-0.4));
#740=DIRECTION('',(0.,0.,1.));
#741=DIRECTION('',(1.,0.,0.));
#742=AXIS2_PLACEMENT_3D('',#739,#740,#741);
#743=CIRCLE('',#742,0.652898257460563);
#744=EDGE_CURVE('E359',#736,#712,#743,.T.);
#745=ORIENTED_EDGE('',*,*,#744,.T.);
#746=ORIENTED_EDGE('',*,*,#713,.T.);
#747=EDGE_LOOP('',(#730,#738,#745,#746));
#748=FACE_BOUND('',#747,.T.);
#749=ADVANCED_FACE('F640',(#748),#729,.T.);
#750=CARTESIAN_POINT('',(80.7740510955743,31.1095236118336,-0.4));
#751=DIRECTION('',(0.966729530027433,-0.255800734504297,0.));
#752=DIRECTION('',(0.255800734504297,0.966729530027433,0.));
#753=AXIS2_PLACEMENT_3D('',#750,#751,#752);
#754=PLANE('',#753);
#755=ORIENTED_EDGE('',*,*,#206,.F.);
#756=DIRECTION('',(0.,0.,1.));
#757=VECTOR('',#756,1.);
#758=CARTESIAN_POINT('',(80.7740510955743,31.1095236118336,-0.4));
#759=LINE('',#758,#757);
#760=CARTESIAN_POINT('',(80.7740510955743,31.1095236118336,-0.4));
#761=VERTEX_POINT('',#760);
#762=EDGE_CURVE('E422',#761,#197,#759,.T.);
#763=ORIENTED_EDGE('',*,*,#762,.F.);
#764=DIRECTION('',(0.255800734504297,0.966729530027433,0.));
#765=VECTOR('',#764,1.);
#766=CARTESIAN_POINT('',(80.7740510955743,31.1095236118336,-0.4));
#767=LINE('',#766,#765);
#768=EDGE_CURVE('E356',#761,#736,#767,.T.);
#769=ORIENTED_EDGE('',*,*,#768,.T.);
#770=ORIENTED_EDGE('',*,*,#737,.T.);
#771=EDGE_LOOP('',(#755,#763,#769,#770));
#772=FACE_BOUND('',#771,.T.);
#773=ADVANCED_FACE('F644',(#772),#754,.T.);
#774=CARTESIAN_POINT('',(81.790227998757,30.9954268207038,-0.4));
#775=DIRECTION('',(0.,0.,1.));
#776=DIRECTION('',(1.,0.,0.));
#777=AXIS2_PLACEMENT_3D('',#774,#775,#776);
#778=CYLINDRICAL_SURFACE('',#777,1.02256226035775);
#779=ORIENTED_EDGE('',*,*,#198,.F.);
#780=DIRECTION('',(0.,0.,1.));
#781=VECTOR('',#780,1.);
#782=CARTESIAN_POINT('',(81.0802834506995,30.2594836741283,-0.4));
#783=LINE('',#782,#781);
#784=CARTESIAN_POINT('',(81.0802834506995,30.2594836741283,-0.4));
#785=VERTEX_POINT('',#784);
#786=EDGE_CURVE('E424',#785,#188,#783,.T.);
#787=ORIENTED_EDGE('',*,*,#786,.F.);
#788=CARTESIAN_POINT('',(81.790227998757,30.9954268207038,-0.4));
#789=DIRECTION('',(0.,0.,-1.));
#790=DIRECTION('',(1.,0.,0.));
#791=AXIS2_PLACEMENT_3D('',#788,#789,#790);
#792=CIRCLE('',#791,1.02256226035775);
#793=EDGE_CURVE('E353',#785,#761,#792,.T.);
#794=ORIENTED_EDGE('',*,*,#793,.T.);
#795=ORIENTED_EDGE('',*,*,#762,.T.);
#796=EDGE_LOOP('',(#779,#787,#794,#795));
#797=FACE_BOUND('',#796,.T.);
#798=ADVANCED_FACE('F648',(#797),#778,.F.);
#799=CARTESIAN_POINT('',(72.2834094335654,20.3510273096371,-0.4));
#800=DIRECTION('',(0.,0.,1.));
#801=DIRECTION('',(1.,0.,0.));
#802=AXIS2_PLACEMENT_3D('',#799,#800,#801);
#803=CYLINDRICAL_SURFACE('',#802,13.2500000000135);
#804=ORIENTED_EDGE('',*,*,#189,.F.);
#805=DIRECTION('',(0.,0.,1.));
#806=VECTOR('',#805,1.);
#807=CARTESIAN_POINT('',(85.5334094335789,20.3510273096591,-0.4));
#808=LINE('',#807,#806);
#809=CARTESIAN_POINT('',(85.5334094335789,20.3510273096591,-0.4));
#810=VERTEX_POINT('',#809);
#811=EDGE_CURVE('E426',#810,#179,#808,.T.);
#812=ORIENTED_EDGE('',*,*,#811,.F.);
#813=CARTESIAN_POINT('',(72.2834094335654,20.3510273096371,-0.4));
#814=DIRECTION('',(0.,0.,1.));
#815=DIRECTION('',(1.,0.,0.));
#816=AXIS2_PLACEMENT_3D('',#813,#814,#815);
#817=CIRCLE('',#816,13.2500000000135);
#818=EDGE_CURVE('E350',#810,#785,#817,.T.);
#819=ORIENTED_EDGE('',*,*,#818,.T.);
#820=ORIENTED_EDGE('',*,*,#786,.T.);
#821=EDGE_LOOP('',(#804,#812,#819,#820));
#822=FACE_BOUND('',#821,.T.);
#823=ADVANCED_FACE('F652',(#822),#803,.T.);
#824=CARTESIAN_POINT('',(85.5334094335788,12.4804227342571,-0.4));
#825=DIRECTION('',(1.,0.,0.));
#826=DIRECTION('',(0.,0.,-1.));
#827=AXIS2_PLACEMENT_3D('',#824,#825,#826);
#828=PLANE('',#827);
#829=ORIENTED_EDGE('',*,*,#180,.F.);
#830=DIRECTION('',(0.,0.,1.));
#831=VECTOR('',#830,1.);
#832=CARTESIAN_POINT('',(85.5334094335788,12.4804227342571,-0.4));
#833=LINE('',#832,#831);
#834=CARTESIAN_POINT('',(85.5334094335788,12.4804227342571,-0.4));
#835=VERTEX_POINT('',#834);
#836=EDGE_CURVE('E428',#835,#171,#833,.T.);
#837=ORIENTED_EDGE('',*,*,#836,.F.);
#838=DIRECTION('',(0.,1.,0.));
#839=VECTOR('',#838,1.);
#840=CARTESIAN_POINT('',(85.5334094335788,12.4804227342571,-0.4));
#841=LINE('',#840,#839);
#842=EDGE_CURVE('E347',#835,#810,#841,.T.);
#843=ORIENTED_EDGE('',*,*,#842,.T.);
#844=ORIENTED_EDGE('',*,*,#811,.T.);
#845=EDGE_LOOP('',(#829,#837,#843,#844));
#846=FACE_BOUND('',#845,.T.);
#847=ADVANCED_FACE('F656',(#846),#828,.T.);
#848=CARTESIAN_POINT('',(84.0134094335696,12.4804227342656,-0.4));
#849=DIRECTION('',(0.,0.,1.));
#850=DIRECTION('',(1.,0.,0.));
#851=AXIS2_PLACEMENT_3D('',#848,#849,#850);
#852=CYLINDRICAL_SURFACE('',#851,1.52000000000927);
#853=ORIENTED_EDGE('',*,*,#172,.F.);
#854=DIRECTION('',(0.,0.,1.));
#855=VECTOR('',#854,1.);
#856=CARTESIAN_POINT('',(84.9489566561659,11.2824446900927,-0.4));
#857=LINE('',#856,#855);
#858=CARTESIAN_POINT('',(84.9489566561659,11.2824446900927,-0.4));
#859=VERTEX_POINT('',#858);
#860=EDGE_CURVE('E430',#859,#162,#857,.T.);
#861=ORIENTED_EDGE('',*,*,#860,.F.);
#862=CARTESIAN_POINT('',(84.0134094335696,12.4804227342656,-0.4));
#863=DIRECTION('',(0.,0.,1.));
#864=DIRECTION('',(1.,0.,0.));
#865=AXIS2_PLACEMENT_3D('',#862,#863,#864);
#866=CIRCLE('',#865,1.52000000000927);
#867=EDGE_CURVE('E344',#859,#835,#866,.T.);
#868=ORIENTED_EDGE('',*,*,#867,.T.);
#869=ORIENTED_EDGE('',*,*,#836,.T.);
#870=EDGE_LOOP('',(#853,#861,#868,#869));
#871=FACE_BOUND('',#870,.T.);
#872=ADVANCED_FACE('F660',(#871),#852,.T.);
#873=CARTESIAN_POINT('',(80.1002135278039,7.4964016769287,-0.4));
#874=DIRECTION('',(0.615438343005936,-0.78818503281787,0.));
#875=DIRECTION('',(0.788185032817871,0.615438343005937,0.));
#876=AXIS2_PLACEMENT_3D('',#873,#874,#875);
#877=PLANE('',#876);
#878=ORIENTED_EDGE('',*,*,#163,.F.);
#879=DIRECTION('',(0.,0.,1.));
#880=VECTOR('',#879,1.);
#881=CARTESIAN_POINT('',(80.1002135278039,7.4964016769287,-0.4));
#882=LINE('',#881,#880);
#883=CARTESIAN_POINT('',(80.1002135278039,7.4964016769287,-0.4));
#884=VERTEX_POINT('',#883);
#885=EDGE_CURVE('E432',#884,#154,#882,.T.);
#886=ORIENTED_EDGE('',*,*,#885,.F.);
#887=DIRECTION('',(0.78818503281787,0.615438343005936,0.));
#888=VECTOR('',#887,1.);
#889=CARTESIAN_POINT('',(80.1002135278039,7.4964016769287,-0.4));
#890=LINE('',#889,#888);
#891=EDGE_CURVE('E341',#884,#859,#890,.T.);
#892=ORIENTED_EDGE('',*,*,#891,.T.);
#893=ORIENTED_EDGE('',*,*,#860,.T.);
#894=EDGE_LOOP('',(#878,#886,#892,#893));
#895=FACE_BOUND('',#894,.T.);
#896=ADVANCED_FACE('F664',(#895),#877,.T.);
#897=CARTESIAN_POINT('',(79.2751515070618,8.50102730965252,-0.4));
#898=DIRECTION('',(0.,0.,1.));
#899=DIRECTION('',(1.,0.,0.));
#900=AXIS2_PLACEMENT_3D('',#897,#898,#899);
#901=CYLINDRICAL_SURFACE('',#900,1.29999999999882);
#902=ORIENTED_EDGE('',*,*,#155,.F.);
#903=DIRECTION('',(0.,0.,1.));
#904=VECTOR('',#903,1.);
#905=CARTESIAN_POINT('',(79.2751515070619,7.2010273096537,-0.4));
#906=LINE('',#905,#904);
#907=CARTESIAN_POINT('',(79.2751515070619,7.2010273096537,-0.4));
#908=VERTEX_POINT('',#907);
#909=EDGE_CURVE('E434',#908,#145,#906,.T.);
#910=ORIENTED_EDGE('',*,*,#909,.F.);
#911=CARTESIAN_POINT('',(79.2751515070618,8.50102730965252,-0.4));
#912=DIRECTION('',(0.,0.,1.));
#913=DIRECTION('',(1.,0.,0.));
#914=AXIS2_PLACEMENT_3D('',#911,#912,#913);
#915=CIRCLE('',#914,1.29999999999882);
#916=EDGE_CURVE('E338',#908,#884,#915,.T.);
#917=ORIENTED_EDGE('',*,*,#916,.T.);
#918=ORIENTED_EDGE('',*,*,#885,.T.);
#919=EDGE_LOOP('',(#902,#910,#917,#918));
#920=FACE_BOUND('',#919,.T.);
#921=ADVANCED_FACE('F668',(#920),#901,.T.);
#922=CARTESIAN_POINT('',(65.4094094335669,7.2010273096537,-0.4));
#923=DIRECTION('',(0.,-1.,0.));
#924=DIRECTION('',(1.,0.,0.));
#925=AXIS2_PLACEMENT_3D('',#922,#923,#924);
#926=PLANE('',#925);
#927=ORIENTED_EDGE('',*,*,#146,.F.);
#928=DIRECTION('',(0.,0.,1.));
#929=VECTOR('',#928,1.);
#930=CARTESIAN_POINT('',(65.4094094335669,7.2010273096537,-0.4));
#931=LINE('',#930,#929);
#932=CARTESIAN_POINT('',(65.4094094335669,7.2010273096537,-0.4));
#933=VERTEX_POINT('',#932);
#934=EDGE_CURVE('E436',#933,#137,#931,.T.);
#935=ORIENTED_EDGE('',*,*,#934,.F.);
#936=DIRECTION('',(1.,0.,0.));
#937=VECTOR('',#936,1.);
#938=CARTESIAN_POINT('',(65.4094094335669,7.2010273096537,-0.4));
#939=LINE('',#938,#937);
#940=EDGE_CURVE('E335',#933,#908,#939,.T.);
#941=ORIENTED_EDGE('',*,*,#940,.T.);
#942=ORIENTED_EDGE('',*,*,#909,.T.);
#943=EDGE_LOOP('',(#927,#935,#941,#942));
#944=FACE_BOUND('',#943,.T.);
#945=ADVANCED_FACE('F672',(#944),#926,.T.);
#946=CARTESIAN_POINT('',(64.1660247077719,7.8552135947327,-0.4));
#947=DIRECTION('',(-0.465620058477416,-0.884984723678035,0.));
#948=DIRECTION('',(0.884984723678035,-0.465620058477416,0.));
#949=AXIS2_PLACEMENT_3D('',#946,#947,#948);
#950=PLANE('',#949);
#951=ORIENTED_EDGE('',*,*,#138,.F.);
#952=DIRECTION('',(0.,0.,1.));
#953=VECTOR('',#952,1.);
#954=CARTESIAN_POINT('',(64.1660247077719,7.8552135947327,-0.4));
#955=LINE('',#954,#953);
#956=CARTESIAN_POINT('',(64.1660247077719,7.8552135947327,-0.4));
#957=VERTEX_POINT('',#956);
#958=EDGE_CURVE('E438',#957,#129,#955,.T.);
#959=ORIENTED_EDGE('',*,*,#958,.F.);
#960=DIRECTION('',(0.884984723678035,-0.465620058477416,0.));
#961=VECTOR('',#960,1.);
#962=CARTESIAN_POINT('',(64.1660247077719,7.8552135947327,-0.4));
#963=LINE('',#962,#961);
#964=EDGE_CURVE('E332',#957,#933,#963,.T.);
#965=ORIENTED_EDGE('',*,*,#964,.T.);
#966=ORIENTED_EDGE('',*,*,#934,.T.);
#967=EDGE_LOOP('',(#951,#959,#965,#966));
#968=FACE_BOUND('',#967,.T.);
#969=ADVANCED_FACE('F676',(#968),#950,.T.);
#970=CARTESIAN_POINT('',(63.6597167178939,6.7821213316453,-0.4));
#971=DIRECTION('',(0.,0.,1.));
#972=DIRECTION('',(1.,0.,0.));
#973=AXIS2_PLACEMENT_3D('',#970,#971,#972);
#974=CYLINDRICAL_SURFACE('',#973,1.18653899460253);
#975=ORIENTED_EDGE('',*,*,#130,.F.);
#976=DIRECTION('',(0.,0.,1.));
#977=VECTOR('',#976,1.);
#978=CARTESIAN_POINT('',(62.713227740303,7.4976864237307,-0.4));
#979=LINE('',#978,#977);
#980=CARTESIAN_POINT('',(62.713227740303,7.4976864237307,-0.4));
#981=VERTEX_POINT('',#980);
#982=EDGE_CURVE('E440',#981,#120,#979,.T.);
#983=ORIENTED_EDGE('',*,*,#982,.F.);
#984=CARTESIAN_POINT('',(63.6597167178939,6.7821213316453,-0.4));
#985=DIRECTION('',(0.,0.,-1.));
#986=DIRECTION('',(1.,0.,0.));
#987=AXIS2_PLACEMENT_3D('',#984,#985,#986);
#988=CIRCLE('',#987,1.18653899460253);
#989=EDGE_CURVE('E329',#981,#957,#988,.T.);
#990=ORIENTED_EDGE('',*,*,#989,.T.);
#991=ORIENTED_EDGE('',*,*,#958,.T.);
#992=EDGE_LOOP('',(#975,#983,#990,#991));
#993=FACE_BOUND('',#992,.T.);
#994=ADVANCED_FACE('F680',(#993),#974,.F.);
#995=CARTESIAN_POINT('',(61.9234094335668,8.11102730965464,-0.4));
#996=DIRECTION('',(0.,0.,1.));
#997=DIRECTION('',(1.,0.,0.));
#998=AXIS2_PLACEMENT_3D('',#995,#996,#997);
#999=CYLINDRICAL_SURFACE('',#998,1.00000000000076);
#1000=ORIENTED_EDGE('',*,*,#121,.F.);
#1001=DIRECTION('',(0.,0.,1.));
#1002=VECTOR('',#1001,1.);
#1003=CARTESIAN_POINT('',(61.2703050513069,7.3537594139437,-0.4));
#1004=LINE('',#1003,#1002);
#1005=CARTESIAN_POINT('',(61.2703050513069,7.3537594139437,-0.4));
#1006=VERTEX_POINT('',#1005);
#1007=EDGE_CURVE('E442',#1006,#111,#1004,.T.);
#1008=ORIENTED_EDGE('',*,*,#1007,.F.);
#1009=CARTESIAN_POINT('',(61.9234094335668,8.11102730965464,-0.4));
#1010=DIRECTION('',(0.,0.,1.));
#1011=DIRECTION('',(1.,0.,0.));
#1012=AXIS2_PLACEMENT_3D('',#1009,#1010,#1011);
#1013=CIRCLE('',#1012,1.00000000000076);
#1014=EDGE_CURVE('E326',#1006,#981,#1013,.T.);
#1015=ORIENTED_EDGE('',*,*,#1014,.T.);
#1016=ORIENTED_EDGE('',*,*,#982,.T.);
#1017=EDGE_LOOP('',(#1000,#1008,#1015,#1016));
#1018=FACE_BOUND('',#1017,.T.);
#1019=ADVANCED_FACE('F684',(#1018),#999,.T.);
#1020=CARTESIAN_POINT('',(59.79093414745,8.6806535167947,-0.4));
#1021=DIRECTION('',(-0.667701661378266,-0.744428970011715,0.));
#1022=DIRECTION('',(0.744428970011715,-0.667701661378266,0.));
#1023=AXIS2_PLACEMENT_3D('',#1020,#1021,#1022);
#1024=PLANE('',#1023);
#1025=ORIENTED_EDGE('',*,*,#112,.F.);
#1026=DIRECTION('',(0.,0.,1.));
#1027=VECTOR('',#1026,1.);
#1028=CARTESIAN_POINT('',(59.79093414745,8.6806535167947,-0.4));
#1029=LINE('',#1028,#1027);
#1030=CARTESIAN_POINT('',(59.79093414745,8.6806535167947,-0.4));
#1031=VERTEX_POINT('',#1030);
#1032=EDGE_CURVE('E444',#1031,#103,#1029,.T.);
#1033=ORIENTED_EDGE('',*,*,#1032,.F.);
#1034=DIRECTION('',(0.744428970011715,-0.667701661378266,0.));
#1035=VECTOR('',#1034,1.);
#1036=CARTESIAN_POINT('',(59.79093414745,8.6806535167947,-0.4));
#1037=LINE('',#1036,#1035);
#1038=EDGE_CURVE('E323',#1031,#1006,#1037,.T.);
#1039=ORIENTED_EDGE('',*,*,#1038,.T.);
#1040=ORIENTED_EDGE('',*,*,#1007,.T.);
#1041=EDGE_LOOP('',(#1025,#1033,#1039,#1040));
#1042=FACE_BOUND('',#1041,.T.);
#1043=ADVANCED_FACE('F688',(#1042),#1024,.T.);
#1044=CARTESIAN_POINT('',(60.3937369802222,9.40788438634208,-0.4));
#1045=DIRECTION('',(0.,0.,1.));
#1046=DIRECTION('',(1.,0.,0.));
#1047=AXIS2_PLACEMENT_3D('',#1044,#1045,#1046);
#1048=CYLINDRICAL_SURFACE('',#1047,0.944582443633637);
#1049=ORIENTED_EDGE('',*,*,#104,.F.);
#1050=DIRECTION('',(0.,0.,1.));
#1051=VECTOR('',#1050,1.);
#1052=CARTESIAN_POINT('',(59.488177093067,9.1391888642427,-0.4));
#1053=LINE('',#1052,#1051);
#1054=CARTESIAN_POINT('',(59.488177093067,9.1391888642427,-0.4));
#1055=VERTEX_POINT('',#1054);
#1056=EDGE_CURVE('E446',#1055,#94,#1053,.T.);
#1057=ORIENTED_EDGE('',*,*,#1056,.F.);
#1058=CARTESIAN_POINT('',(60.3937369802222,9.40788438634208,-0.4));
#1059=DIRECTION('',(0.,0.,1.));
#1060=DIRECTION('',(1.,0.,0.));
#1061=AXIS2_PLACEMENT_3D('',#1058,#1059,#1060);
#1062=CIRCLE('',#1061,0.944582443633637);
#1063=EDGE_CURVE('E320',#1055,#1031,#1062,.T.);
#1064=ORIENTED_EDGE('',*,*,#1063,.T.);
#1065=ORIENTED_EDGE('',*,*,#1032,.T.);
#1066=EDGE_LOOP('',(#1049,#1057,#1064,#1065));
#1067=FACE_BOUND('',#1066,.T.);
#1068=ADVANCED_FACE('F692',(#1067),#1048,.T.);
#1069=CARTESIAN_POINT('',(59.033409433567,12.3510273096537,-0.4));
#1070=DIRECTION('',(-0.990124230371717,-0.140192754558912,0.));
#1071=DIRECTION('',(0.140192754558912,-0.990124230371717,0.));
#1072=AXIS2_PLACEMENT_3D('',#1069,#1070,#1071);
#1073=PLANE('',#1072);
#1074=ORIENTED_EDGE('',*,*,#95,.F.);
#1075=DIRECTION('',(0.,0.,1.));
#1076=VECTOR('',#1075,1.);
#1077=CARTESIAN_POINT('',(59.033409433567,12.3510273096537,-0.4));
#1078=LINE('',#1077,#1076);
#1079=CARTESIAN_POINT('',(59.033409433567,12.3510273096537,-0.4));
#1080=VERTEX_POINT('',#1079);
#1081=EDGE_CURVE('E216',#1080,#86,#1078,.T.);
#1082=ORIENTED_EDGE('',*,*,#1081,.F.);
#1083=DIRECTION('',(0.140192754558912,-0.990124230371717,0.));
#1084=VECTOR('',#1083,1.);
#1085=CARTESIAN_POINT('',(59.033409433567,12.3510273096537,-0.4));
#1086=LINE('',#1085,#1084);
#1087=EDGE_CURVE('E317',#1080,#1055,#1086,.T.);
#1088=ORIENTED_EDGE('',*,*,#1087,.T.);
#1089=ORIENTED_EDGE('',*,*,#1056,.T.);
#1090=EDGE_LOOP('',(#1074,#1082,#1088,#1089));
#1091=FACE_BOUND('',#1090,.T.);
#1092=ADVANCED_FACE('F696',(#1091),#1073,.T.);
#1093=CARTESIAN_POINT('',(59.0334094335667,20.3510273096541,-0.4));
#1094=DIRECTION('',(-1.,0.,0.));
#1095=DIRECTION('',(0.,-1.,0.));
#1096=AXIS2_PLACEMENT_3D('',#1093,#1094,#1095);
#1097=PLANE('',#1096);
#1098=ORIENTED_EDGE('',*,*,#87,.F.);
#1099=ORIENTED_EDGE('',*,*,#425,.F.);
#1100=DIRECTION('',(0.,-1.,0.));
#1101=VECTOR('',#1100,1.);
#1102=CARTESIAN_POINT('',(59.0334094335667,20.3510273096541,-0.4));
#1103=LINE('',#1102,#1101);
#1104=EDGE_CURVE('E315',#418,#1080,#1103,.T.);
#1105=ORIENTED_EDGE('',*,*,#1104,.T.);
#1106=ORIENTED_EDGE('',*,*,#1081,.T.);
#1107=EDGE_LOOP('',(#1098,#1099,#1105,#1106));
#1108=FACE_BOUND('',#1107,.T.);
#1109=ADVANCED_FACE('F221',(#1108),#1097,.T.);
#1110=CARTESIAN_POINT('',(72.2071972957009,20.3682152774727,-0.4));
#1111=DIRECTION('',(0.,0.,1.));
#1112=DIRECTION('',(1.,0.,0.));
#1113=AXIS2_PLACEMENT_3D('',#1110,#1111,#1112);
#1114=PLANE('',#1113);
#1115=CARTESIAN_POINT('',(72.2834094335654,20.3510273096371,-0.4));
#1116=DIRECTION('',(0.,0.,1.));
#1117=DIRECTION('',(1.,0.,0.));
#1118=AXIS2_PLACEMENT_3D('',#1115,#1116,#1117);
#1119=CIRCLE('',#1118,8.99999999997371);
#1120=CARTESIAN_POINT('',(81.2834094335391,20.3510273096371,-0.4));
#1121=VERTEX_POINT('',#1120);
#1122=EDGE_CURVE('E493',#1121,#1121,#1119,.T.);
#1123=ORIENTED_EDGE('',*,*,#1122,.T.);
#1124=EDGE_LOOP('',(#1123));
#1125=FACE_BOUND('',#1124,.T.);
#1126=CARTESIAN_POINT('',(61.9234094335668,8.11102730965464,-0.4));
#1127=DIRECTION('',(0.,0.,1.));
#1128=DIRECTION('',(1.,0.,0.));
#1129=AXIS2_PLACEMENT_3D('',#1126,#1127,#1128);
#1130=CIRCLE('',#1129,0.330000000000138);
#1131=CARTESIAN_POINT('',(62.2534094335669,8.11102730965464,-0.4));
#1132=VERTEX_POINT('',#1131);
#1133=EDGE_CURVE('E499',#1132,#1132,#1130,.T.);
#1134=ORIENTED_EDGE('',*,*,#1133,.T.);
#1135=EDGE_LOOP('',(#1134));
#1136=FACE_BOUND('',#1135,.T.);
#1137=CARTESIAN_POINT('',(60.444488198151,9.4315398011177,-0.4));
#1138=DIRECTION('',(0.,0.,1.));
#1139=DIRECTION('',(1.,0.,0.));
#1140=AXIS2_PLACEMENT_3D('',#1137,#1138,#1139);
#1141=CIRCLE('',#1140,0.33);
#1142=CARTESIAN_POINT('',(60.774488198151,9.4315398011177,-0.4));
#1143=VERTEX_POINT('',#1142);
#1144=EDGE_CURVE('E505',#1143,#1143,#1141,.T.);
#1145=ORIENTED_EDGE('',*,*,#1144,.T.);
#1146=EDGE_LOOP('',(#1145));
#1147=FACE_BOUND('',#1146,.T.);
#1148=CARTESIAN_POINT('',(60.553409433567,12.4810273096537,-0.4));
#1149=DIRECTION('',(0.,0.,1.));
#1150=DIRECTION('',(1.,0.,0.));
#1151=AXIS2_PLACEMENT_3D('',#1148,#1149,#1150);
#1152=CIRCLE('',#1151,0.8);
#1153=CARTESIAN_POINT('',(61.353409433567,12.4810273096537,-0.4));
#1154=VERTEX_POINT('',#1153);
#1155=EDGE_CURVE('E511',#1154,#1154,#1152,.T.);
#1156=ORIENTED_EDGE('',*,*,#1155,.T.);
#1157=EDGE_LOOP('',(#1156));
#1158=FACE_BOUND('',#1157,.T.);
#1159=CARTESIAN_POINT('',(61.633409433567,10.8310273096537,-0.4));
#1160=DIRECTION('',(0.,0.,1.));
#1161=DIRECTION('',(1.,0.,0.));
#1162=AXIS2_PLACEMENT_3D('',#1159,#1160,#1161);
#1163=CIRCLE('',#1162,0.8);
#1164=CARTESIAN_POINT('',(62.433409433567,10.8310273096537,-0.4));
#1165=VERTEX_POINT('',#1164);
#1166=EDGE_CURVE('E517',#1165,#1165,#1163,.T.);
#1167=ORIENTED_EDGE('',*,*,#1166,.T.);
#1168=EDGE_LOOP('',(#1167));
#1169=FACE_BOUND('',#1168,.T.);
#1170=CARTESIAN_POINT('',(63.4734094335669,9.2810273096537,-0.4));
#1171=DIRECTION('',(0.,0.,1.));
#1172=DIRECTION('',(1.,0.,0.));
#1173=AXIS2_PLACEMENT_3D('',#1170,#1171,#1172);
#1174=CIRCLE('',#1173,0.8);
#1175=CARTESIAN_POINT('',(64.2734094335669,9.2810273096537,-0.4));
#1176=VERTEX_POINT('',#1175);
#1177=EDGE_CURVE('E523',#1176,#1176,#1174,.T.);
#1178=ORIENTED_EDGE('',*,*,#1177,.T.);
#1179=EDGE_LOOP('',(#1178));
#1180=FACE_BOUND('',#1179,.T.);
#1181=CARTESIAN_POINT('',(84.0134094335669,12.4810273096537,-0.4));
#1182=DIRECTION('',(0.,0.,1.));
#1183=DIRECTION('',(1.,0.,0.));
#1184=AXIS2_PLACEMENT_3D('',#1181,#1182,#1183);
#1185=CIRCLE('',#1184,0.8);
#1186=CARTESIAN_POINT('',(84.8134094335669,12.4810273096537,-0.4));
#1187=VERTEX_POINT('',#1186);
#1188=EDGE_CURVE('E231',#1187,#1187,#1185,.T.);
#1189=ORIENTED_EDGE('',*,*,#1188,.T.);
#1190=EDGE_LOOP('',(#1189));
#1191=FACE_BOUND('',#1190,.T.);
#1192=ORIENTED_EDGE('',*,*,#419,.F.);
#1193=ORIENTED_EDGE('',*,*,#449,.F.);
#1194=ORIENTED_EDGE('',*,*,#473,.F.);
#1195=ORIENTED_EDGE('',*,*,#498,.F.);
#1196=ORIENTED_EDGE('',*,*,#522,.F.);
#1197=ORIENTED_EDGE('',*,*,#547,.F.);
#1198=ORIENTED_EDGE('',*,*,#571,.F.);
#1199=ORIENTED_EDGE('',*,*,#596,.F.);
#1200=ORIENTED_EDGE('',*,*,#621,.F.);
#1201=ORIENTED_EDGE('',*,*,#646,.F.);
#1202=ORIENTED_EDGE('',*,*,#670,.F.);
#1203=ORIENTED_EDGE('',*,*,#695,.F.);
#1204=ORIENTED_EDGE('',*,*,#719,.F.);
#1205=ORIENTED_EDGE('',*,*,#744,.F.);
#1206=ORIENTED_EDGE('',*,*,#768,.F.);
#1207=ORIENTED_EDGE('',*,*,#793,.F.);
#1208=ORIENTED_EDGE('',*,*,#818,.F.);
#1209=ORIENTED_EDGE('',*,*,#842,.F.);
#1210=ORIENTED_EDGE('',*,*,#867,.F.);
#1211=ORIENTED_EDGE('',*,*,#891,.F.);
#1212=ORIENTED_EDGE('',*,*,#916,.F.);
#1213=ORIENTED_EDGE('',*,*,#940,.F.);
#1214=ORIENTED_EDGE('',*,*,#964,.F.);
#1215=ORIENTED_EDGE('',*,*,#989,.F.);
#1216=ORIENTED_EDGE('',*,*,#1014,.F.);
#1217=ORIENTED_EDGE('',*,*,#1038,.F.);
#1218=ORIENTED_EDGE('',*,*,#1063,.F.);
#1219=ORIENTED_EDGE('',*,*,#1087,.F.);
#1220=ORIENTED_EDGE('',*,*,#1104,.F.);
#1221=EDGE_LOOP('',(#1192,#1193,#1194,#1195,#1196,#1197,#1198,#1199,#1200,#1201,#1202,#1203,
#1204,#1205,#1206,#1207,#1208,#1209,#1210,#1211,#1212,#1213,#1214,#1215,#1216,#1217,#1218,#1219,#1220));
#1222=FACE_BOUND('',#1221,.T.);
#1223=ADVANCED_FACE('F589',(#1125,#1136,#1147,#1158,#1169,#1180,#1191,#1222),#1114,.F.);
#1224=CARTESIAN_POINT('',(72.2834094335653,20.3510273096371,0.));
#1225=DIRECTION('',(0.,0.,1.));
#1226=DIRECTION('',(1.,0.,0.));
#1227=AXIS2_PLACEMENT_3D('',#1224,#1225,#1226);
#1228=CIRCLE('',#1227,9.30000000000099);
#1229=CARTESIAN_POINT('',(81.5834094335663,20.3510273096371,0.));
#1230=VERTEX_POINT('',#1229);
#1231=EDGE_CURVE('E11',#1230,#1230,#1228,.F.);
#1232=ORIENTED_EDGE('',*,*,#1231,.F.);
#1233=EDGE_LOOP('',(#1232));
#1234=FACE_BOUND('',#1233,.T.);
#1235=CARTESIAN_POINT('',(72.2834094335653,20.3510273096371,0.));
#1236=DIRECTION('',(0.,0.,1.));
#1237=DIRECTION('',(1.,0.,0.));
#1238=AXIS2_PLACEMENT_3D('',#1235,#1236,#1237);
#1239=CIRCLE('',#1238,8.99999999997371);
#1240=CARTESIAN_POINT('',(81.283409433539,20.3510273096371,0.));
#1241=VERTEX_POINT('',#1240);
#1242=EDGE_CURVE('E490',#1241,#1241,#1239,.T.);
#1243=ORIENTED_EDGE('',*,*,#1242,.F.);
#1244=EDGE_LOOP('',(#1243));
#1245=FACE_BOUND('',#1244,.T.);
#1246=ADVANCED_FACE('F459',(#1234,#1245),#23,.T.);
#1247=CARTESIAN_POINT('',(84.0134094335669,12.4810273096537,-0.4));
#1248=DIRECTION('',(0.,0.,1.));
#1249=DIRECTION('',(1.,0.,0.));
#1250=AXIS2_PLACEMENT_3D('',#1247,#1248,#1249);
#1251=CYLINDRICAL_SURFACE('',#1250,0.8);
#1252=ORIENTED_EDGE('',*,*,#1188,.F.);
#1253=EDGE_LOOP('',(#1252));
#1254=FACE_BOUND('',#1253,.T.);
#1255=ORIENTED_EDGE('',*,*,#327,.T.);
#1256=EDGE_LOOP('',(#1255));
#1257=FACE_BOUND('',#1256,.T.);
#1258=ADVANCED_FACE('F528',(#1254,#1257),#1251,.F.);
#1259=CARTESIAN_POINT('',(63.4734094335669,9.2810273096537,-0.4));
#1260=DIRECTION('',(0.,0.,1.));
#1261=DIRECTION('',(1.,0.,0.));
#1262=AXIS2_PLACEMENT_3D('',#1259,#1260,#1261);
#1263=CYLINDRICAL_SURFACE('',#1262,0.8);
#1264=ORIENTED_EDGE('',*,*,#1177,.F.);
#1265=EDGE_LOOP('',(#1264));
#1266=FACE_BOUND('',#1265,.T.);
#1267=ORIENTED_EDGE('',*,*,#338,.T.);
#1268=EDGE_LOOP('',(#1267));
#1269=FACE_BOUND('',#1268,.T.);
#1270=ADVANCED_FACE('F580',(#1266,#1269),#1263,.F.);
#1271=CARTESIAN_POINT('',(61.633409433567,10.8310273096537,-0.4));
#1272=DIRECTION('',(0.,0.,1.));
#1273=DIRECTION('',(1.,0.,0.));
#1274=AXIS2_PLACEMENT_3D('',#1271,#1272,#1273);
#1275=CYLINDRICAL_SURFACE('',#1274,0.8);
#1276=ORIENTED_EDGE('',*,*,#1166,.F.);
#1277=EDGE_LOOP('',(#1276));
#1278=FACE_BOUND('',#1277,.T.);
#1279=ORIENTED_EDGE('',*,*,#349,.T.);
#1280=EDGE_LOOP('',(#1279));
#1281=FACE_BOUND('',#1280,.T.);
#1282=ADVANCED_FACE('F576',(#1278,#1281),#1275,.F.);
#1283=CARTESIAN_POINT('',(60.553409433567,12.4810273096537,-0.4));
#1284=DIRECTION('',(0.,0.,1.));
#1285=DIRECTION('',(1.,0.,0.));
#1286=AXIS2_PLACEMENT_3D('',#1283,#1284,#1285);
#1287=CYLINDRICAL_SURFACE('',#1286,0.8);
#1288=ORIENTED_EDGE('',*,*,#1155,.F.);
#1289=EDGE_LOOP('',(#1288));
#1290=FACE_BOUND('',#1289,.T.);
#1291=ORIENTED_EDGE('',*,*,#360,.T.);
#1292=EDGE_LOOP('',(#1291));
#1293=FACE_BOUND('',#1292,.T.);
#1294=ADVANCED_FACE('F572',(#1290,#1293),#1287,.F.);
#1295=CARTESIAN_POINT('',(60.444488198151,9.4315398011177,-0.4));
#1296=DIRECTION('',(0.,0.,1.));
#1297=DIRECTION('',(1.,0.,0.));
#1298=AXIS2_PLACEMENT_3D('',#1295,#1296,#1297);
#1299=CYLINDRICAL_SURFACE('',#1298,0.33);
#1300=ORIENTED_EDGE('',*,*,#1144,.F.);
#1301=EDGE_LOOP('',(#1300));
#1302=FACE_BOUND('',#1301,.T.);
#1303=ORIENTED_EDGE('',*,*,#371,.T.);
#1304=EDGE_LOOP('',(#1303));
#1305=FACE_BOUND('',#1304,.T.);
#1306=ADVANCED_FACE('F568',(#1302,#1305),#1299,.F.);
#1307=CARTESIAN_POINT('',(61.9234094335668,8.11102730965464,-0.4));
#1308=DIRECTION('',(0.,0.,1.));
#1309=DIRECTION('',(1.,0.,0.));
#1310=AXIS2_PLACEMENT_3D('',#1307,#1308,#1309);
#1311=CYLINDRICAL_SURFACE('',#1310,0.330000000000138);
#1312=ORIENTED_EDGE('',*,*,#1133,.F.);
#1313=EDGE_LOOP('',(#1312));
#1314=FACE_BOUND('',#1313,.T.);
#1315=ORIENTED_EDGE('',*,*,#382,.T.);
#1316=EDGE_LOOP('',(#1315));
#1317=FACE_BOUND('',#1316,.T.);
#1318=ADVANCED_FACE('F564',(#1314,#1317),#1311,.F.);
#1319=CARTESIAN_POINT('',(72.2834094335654,20.3510273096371,-0.4));
#1320=DIRECTION('',(0.,0.,1.));
#1321=DIRECTION('',(1.,0.,0.));
#1322=AXIS2_PLACEMENT_3D('',#1319,#1320,#1321);
#1323=CYLINDRICAL_SURFACE('',#1322,8.99999999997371);
#1324=ORIENTED_EDGE('',*,*,#1122,.F.);
#1325=EDGE_LOOP('',(#1324));
#1326=FACE_BOUND('',#1325,.T.);
#1327=ORIENTED_EDGE('',*,*,#1242,.T.);
#1328=EDGE_LOOP('',(#1327));
#1329=FACE_BOUND('',#1328,.T.);
#1330=ADVANCED_FACE('F556',(#1326,#1329),#1323,.F.);
#1331=CARTESIAN_POINT('',(72.2834094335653,20.3510273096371,0.00999999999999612));
#1332=DIRECTION('',(0.,0.,-1.));
#1333=DIRECTION('',(-1.,0.,0.));
#1334=AXIS2_PLACEMENT_3D('',#1331,#1332,#1333);
#1335=CYLINDRICAL_SURFACE('',#1334,11.9);
#1336=CARTESIAN_POINT('',(72.2834094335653,20.3510273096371,0.00999999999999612));
#1337=DIRECTION('',(0.,0.,1.));
#1338=DIRECTION('',(1.,0.,0.));
#1339=AXIS2_PLACEMENT_3D('',#1336,#1337,#1338);
#1340=CIRCLE('',#1339,11.9);
#1341=CARTESIAN_POINT('',(84.1834094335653,20.3510273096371,0.00999999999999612));
#1342=VERTEX_POINT('',#1341);
#1343=EDGE_CURVE('E484',#1342,#1342,#1340,.T.);
#1344=ORIENTED_EDGE('',*,*,#1343,.T.);
#1345=EDGE_LOOP('',(#1344));
#1346=FACE_BOUND('',#1345,.T.);
#1347=ORIENTED_EDGE('',*,*,#54,.T.);
#1348=EDGE_LOOP('',(#1347));
#1349=FACE_BOUND('',#1348,.T.);
#1350=ADVANCED_FACE('F546',(#1346,#1349),#1335,.F.);
#1351=CARTESIAN_POINT('',(72.2834094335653,20.3510273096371,0.00999999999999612));
#1352=DIRECTION('',(0.,0.,-1.));
#1353=DIRECTION('',(-1.,0.,0.));
#1354=AXIS2_PLACEMENT_3D('',#1351,#1352,#1353);
#1355=CYLINDRICAL_SURFACE('',#1354,12.9);
#1356=CARTESIAN_POINT('',(72.2834094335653,20.3510273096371,0.00999999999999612));
#1357=DIRECTION('',(0.,0.,1.));
#1358=DIRECTION('',(1.,0.,0.));
#1359=AXIS2_PLACEMENT_3D('',#1356,#1357,#1358);
#1360=CIRCLE('',#1359,12.9);
#1361=CARTESIAN_POINT('',(85.1834094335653,20.3510273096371,0.00999999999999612));
#1362=VERTEX_POINT('',#1361);
#1363=EDGE_CURVE('E487',#1362,#1362,#1360,.T.);
#1364=ORIENTED_EDGE('',*,*,#1363,.F.);
#1365=EDGE_LOOP('',(#1364));
#1366=FACE_BOUND('',#1365,.T.);
#1367=ORIENTED_EDGE('',*,*,#393,.T.);
#1368=EDGE_LOOP('',(#1367));
#1369=FACE_BOUND('',#1368,.T.);
#1370=ADVANCED_FACE('F543',(#1366,#1369),#1355,.T.);
#1371=CARTESIAN_POINT('',(72.2834094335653,-8.17039404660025,0.00999999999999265));
#1372=DIRECTION('',(0.,0.,1.));
#1373=DIRECTION('',(1.,0.,0.));
#1374=AXIS2_PLACEMENT_3D('',#1371,#1372,#1373);
#1375=PLANE('',#1374);
#1376=ORIENTED_EDGE('',*,*,#1343,.F.);
#1377=EDGE_LOOP('',(#1376));
#1378=FACE_BOUND('',#1377,.T.);
#1379=ORIENTED_EDGE('',*,*,#1363,.T.);
#1380=EDGE_LOOP('',(#1379));
#1381=FACE_BOUND('',#1380,.T.);
#1382=ADVANCED_FACE('F545',(#1378,#1381),#1375,.T.);
#1383=CARTESIAN_POINT('',(72.2834094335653,20.3510273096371,0.00999999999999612));
#1384=DIRECTION('',(0.,0.,-1.));
#1385=DIRECTION('',(-1.,0.,0.));
#1386=AXIS2_PLACEMENT_3D('',#1383,#1384,#1385);
#1387=CYLINDRICAL_SURFACE('',#1386,10.);
#1388=CARTESIAN_POINT('',(72.2834094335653,20.3510273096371,0.00999999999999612));
#1389=DIRECTION('',(0.,0.,1.));
#1390=DIRECTION('',(1.,0.,0.));
#1391=AXIS2_PLACEMENT_3D('',#1388,#1389,#1390);
#1392=CIRCLE('',#1391,10.);
#1393=CARTESIAN_POINT('',(82.2834094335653,20.3510273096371,0.00999999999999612));
#1394=VERTEX_POINT('',#1393);
#1395=EDGE_CURVE('E475',#1394,#1394,#1392,.T.);
#1396=ORIENTED_EDGE('',*,*,#1395,.T.);
#1397=EDGE_LOOP('',(#1396));
#1398=FACE_BOUND('',#1397,.T.);
#1399=ORIENTED_EDGE('',*,*,#31,.T.);
#1400=EDGE_LOOP('',(#1399));
#1401=FACE_BOUND('',#1400,.T.);
#1402=ADVANCED_FACE('F453',(#1398,#1401),#1387,.F.);
#1403=CARTESIAN_POINT('',(72.2071972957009,20.3682152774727,0.00999999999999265));
#1404=DIRECTION('',(0.,0.,-1.));
#1405=DIRECTION('',(-1.,0.,0.));
#1406=AXIS2_PLACEMENT_3D('',#1403,#1404,#1405);
#1407=CYLINDRICAL_SURFACE('',#1406,11.1);
#1408=CARTESIAN_POINT('',(72.2071972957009,20.3682152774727,0.00999999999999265));
#1409=DIRECTION('',(0.,0.,1.));
#1410=DIRECTION('',(1.,0.,0.));
#1411=AXIS2_PLACEMENT_3D('',#1408,#1409,#1410);
#1412=CIRCLE('',#1411,11.1);
#1413=CARTESIAN_POINT('',(83.3071972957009,20.3682152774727,0.00999999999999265));
#1414=VERTEX_POINT('',#1413);
#1415=EDGE_CURVE('E478',#1414,#1414,#1412,.T.);
#1416=ORIENTED_EDGE('',*,*,#1415,.F.);
#1417=EDGE_LOOP('',(#1416));
#1418=FACE_BOUND('',#1417,.T.);
#1419=ORIENTED_EDGE('',*,*,#65,.T.);
#1420=EDGE_LOOP('',(#1419));
#1421=FACE_BOUND('',#1420,.T.);
#1422=ADVANCED_FACE('F784',(#1418,#1421),#1407,.T.);
#1423=CARTESIAN_POINT('',(72.2834094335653,-8.17039404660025,0.00999999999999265));
#1424=DIRECTION('',(0.,0.,1.));
#1425=DIRECTION('',(1.,0.,0.));
#1426=AXIS2_PLACEMENT_3D('',#1423,#1424,#1425);
#1427=PLANE('',#1426);
#1428=ORIENTED_EDGE('',*,*,#1395,.F.);
#1429=EDGE_LOOP('',(#1428));
#1430=FACE_BOUND('',#1429,.T.);
#1431=ORIENTED_EDGE('',*,*,#1415,.T.);
#1432=EDGE_LOOP('',(#1431));
#1433=FACE_BOUND('',#1432,.T.);
#1434=ADVANCED_FACE('F794',(#1430,#1433),#1427,.T.);
#1435=CARTESIAN_POINT('',(72.2834094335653,20.3510273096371,0.00999999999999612));
#1436=DIRECTION('',(0.,0.,-1.));
#1437=DIRECTION('',(-1.,0.,0.));
#1438=AXIS2_PLACEMENT_3D('',#1435,#1436,#1437);
#1439=CYLINDRICAL_SURFACE('',#1438,9.30000000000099);
#1440=CARTESIAN_POINT('',(72.2834094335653,20.3510273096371,0.00999999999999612));
#1441=DIRECTION('',(0.,0.,1.));
#1442=DIRECTION('',(1.,0.,0.));
#1443=AXIS2_PLACEMENT_3D('',#1440,#1441,#1442);
#1444=CIRCLE('',#1443,9.30000000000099);
#1445=CARTESIAN_POINT('',(81.5834094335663,20.3510273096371,0.00999999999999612));
#1446=VERTEX_POINT('',#1445);
#1447=EDGE_CURVE('E464',#1446,#1446,#1444,.T.);
#1448=ORIENTED_EDGE('',*,*,#1447,.T.);
#1449=EDGE_LOOP('',(#1448));
#1450=FACE_BOUND('',#1449,.T.);
#1451=ORIENTED_EDGE('',*,*,#1231,.T.);
#1452=EDGE_LOOP('',(#1451));
#1453=FACE_BOUND('',#1452,.T.);
#1454=ADVANCED_FACE('F805',(#1450,#1453),#1439,.F.);
#1455=CARTESIAN_POINT('',(72.2834094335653,20.3510273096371,0.00999999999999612));
#1456=DIRECTION('',(0.,0.,-1.));
#1457=DIRECTION('',(-1.,0.,0.));
#1458=AXIS2_PLACEMENT_3D('',#1455,#1456,#1457);
#1459=CYLINDRICAL_SURFACE('',#1458,9.79999999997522);
#1460=CARTESIAN_POINT('',(72.2834094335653,20.3510273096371,0.00999999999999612));
#1461=DIRECTION('',(0.,0.,1.));
#1462=DIRECTION('',(1.,0.,0.));
#1463=AXIS2_PLACEMENT_3D('',#1460,#1461,#1462);
#1464=CIRCLE('',#1463,9.79999999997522);
#1465=CARTESIAN_POINT('',(82.0834094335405,20.3510273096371,0.00999999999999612));
#1466=VERTEX_POINT('',#1465);
#1467=EDGE_CURVE('E467',#1466,#1466,#1464,.T.);
#1468=ORIENTED_EDGE('',*,*,#1467,.F.);
#1469=EDGE_LOOP('',(#1468));
#1470=FACE_BOUND('',#1469,.T.);
#1471=ORIENTED_EDGE('',*,*,#42,.T.);
#1472=EDGE_LOOP('',(#1471));
#1473=FACE_BOUND('',#1472,.T.);
#1474=ADVANCED_FACE('F816',(#1470,#1473),#1459,.T.);
#1475=CARTESIAN_POINT('',(72.2834094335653,-8.17039404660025,0.00999999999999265));
#1476=DIRECTION('',(0.,0.,1.));
#1477=DIRECTION('',(1.,0.,0.));
#1478=AXIS2_PLACEMENT_3D('',#1475,#1476,#1477);
#1479=PLANE('',#1478);
#1480=ORIENTED_EDGE('',*,*,#1447,.F.);
#1481=EDGE_LOOP('',(#1480));
#1482=FACE_BOUND('',#1481,.T.);
#1483=ORIENTED_EDGE('',*,*,#1467,.T.);
#1484=EDGE_LOOP('',(#1483));
#1485=FACE_BOUND('',#1484,.T.);
#1486=ADVANCED_FACE('F827',(#1482,#1485),#1479,.T.);
#1487=CLOSED_SHELL('',(#46,#69,#397,#429,#454,#478,#503,#527,#552,#576,#601,#626,#651,#675,#700,
#724,#749,#773,#798,#823,#847,#872,#896,#921,#945,#969,#994,#1019,#1043,#1068,#1092,#1109,#1223,
#1246,#1258,#1270,#1282,#1294,#1306,#1318,#1330,#1350,#1370,#1382,#1402,#1422,#1434,#1454,#1474,#1486));
#1488=MANIFOLD_SOLID_BREP('B1',#1487);
#1489=ADVANCED_BREP_SHAPE_REPRESENTATION('',(#18,#1488),#14);
#1490=SHAPE_DEFINITION_REPRESENTATION(#9,#1489);
ENDSEC;
END-ISO-10303-21;
